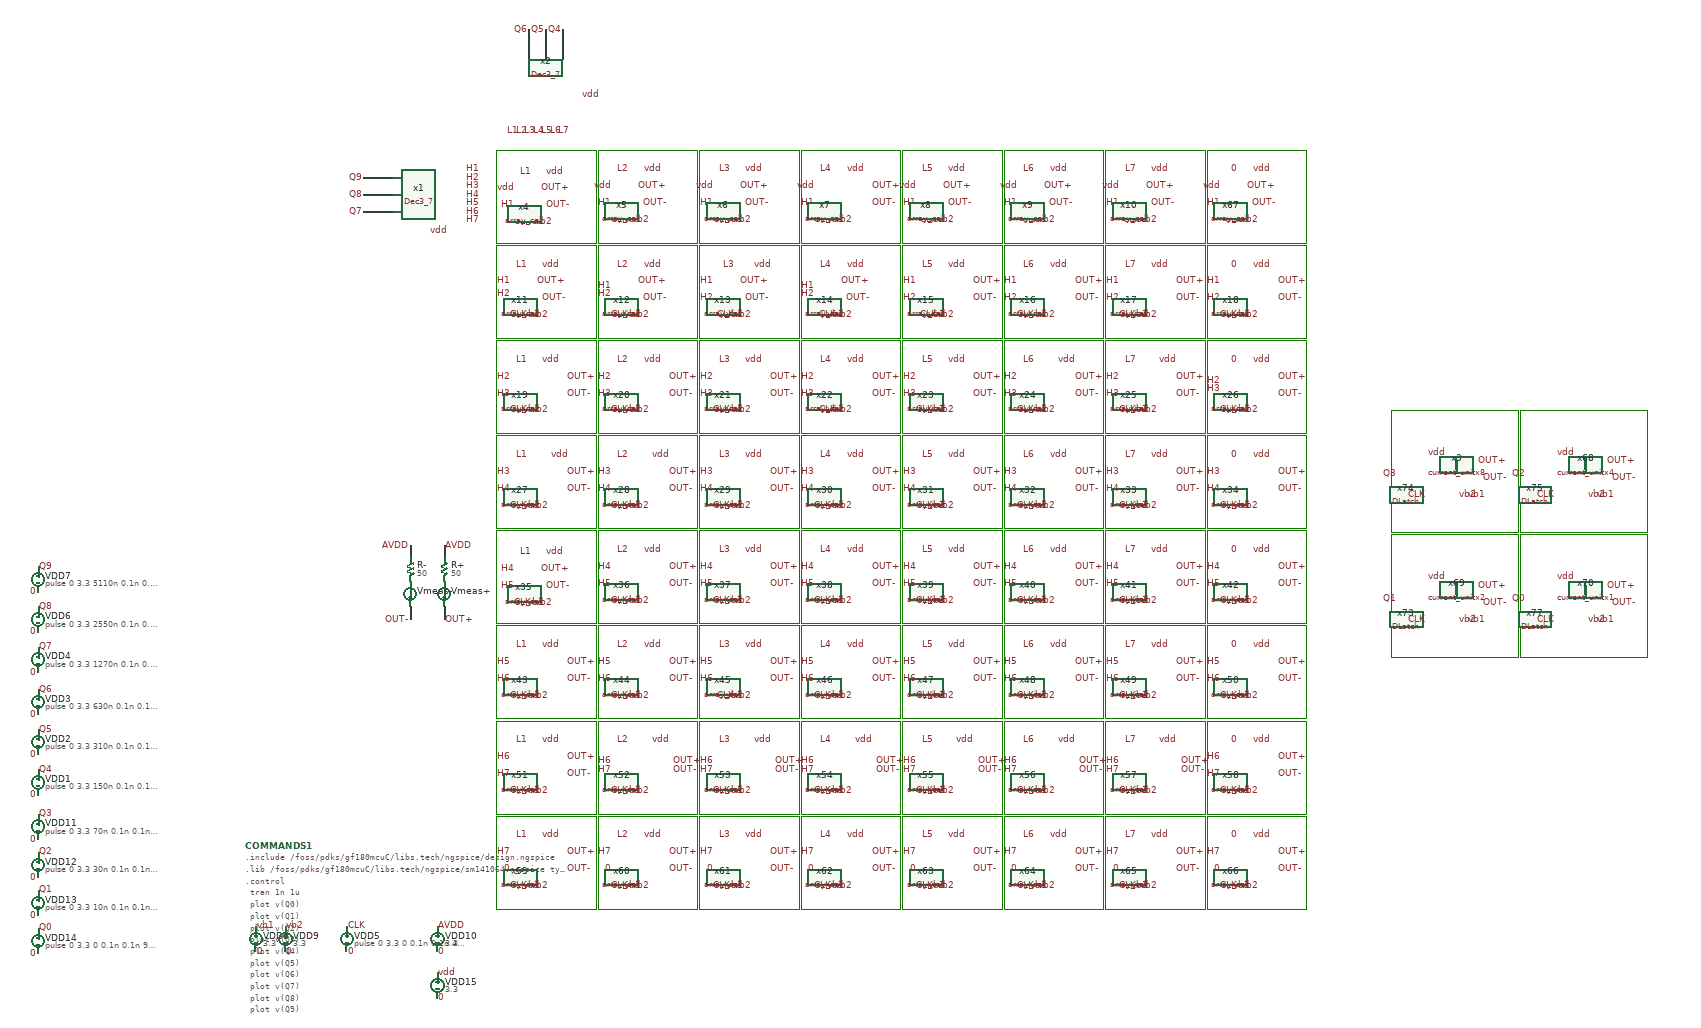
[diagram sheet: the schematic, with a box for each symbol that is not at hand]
v {xschem version=3.1.0 file_version=1.2
}
G {}
K {}
V {}
S {}
E {}
L 4 40 -1675 235 -1675 {}
L 4 235 -1895 235 -1675 {}
L 4 40 -1895 235 -1895 {}
L 4 0 -1895 40 -1895 {}
L 4 0 -1675 40 -1675 {}
L 4 0 -1895 0 -1675 {}
L 4 280 -1675 475 -1675 {}
L 4 475 -1895 475 -1675 {}
L 4 280 -1895 475 -1895 {}
L 4 240 -1895 280 -1895 {}
L 4 240 -1675 280 -1675 {}
L 4 240 -1895 240 -1675 {}
L 4 520 -1675 715 -1675 {}
L 4 715 -1895 715 -1675 {}
L 4 520 -1895 715 -1895 {}
L 4 480 -1895 520 -1895 {}
L 4 480 -1675 520 -1675 {}
L 4 480 -1895 480 -1675 {}
L 4 760 -1675 955 -1675 {}
L 4 955 -1895 955 -1675 {}
L 4 760 -1895 955 -1895 {}
L 4 720 -1895 760 -1895 {}
L 4 720 -1675 760 -1675 {}
L 4 720 -1895 720 -1675 {}
L 4 1000 -1675 1195 -1675 {}
L 4 1195 -1895 1195 -1675 {}
L 4 1000 -1895 1195 -1895 {}
L 4 960 -1895 1000 -1895 {}
L 4 960 -1675 1000 -1675 {}
L 4 960 -1895 960 -1675 {}
L 4 1240 -1675 1435 -1675 {}
L 4 1435 -1895 1435 -1675 {}
L 4 1240 -1895 1435 -1895 {}
L 4 1200 -1895 1240 -1895 {}
L 4 1200 -1675 1240 -1675 {}
L 4 1200 -1895 1200 -1675 {}
L 4 1480 -1675 1675 -1675 {}
L 4 1675 -1895 1675 -1675 {}
L 4 1480 -1895 1675 -1895 {}
L 4 1440 -1895 1480 -1895 {}
L 4 1440 -1675 1480 -1675 {}
L 4 1440 -1895 1440 -1675 {}
L 4 1720 -1675 1915 -1675 {}
L 4 1915 -1895 1915 -1675 {}
L 4 1720 -1895 1915 -1895 {}
L 4 1680 -1895 1720 -1895 {}
L 4 1680 -1675 1720 -1675 {}
L 4 1680 -1895 1680 -1675 {}
L 4 40 -1450 235 -1450 {}
L 4 235 -1670 235 -1450 {}
L 4 40 -1670 235 -1670 {}
L 4 0 -1670 40 -1670 {}
L 4 0 -1450 40 -1450 {}
L 4 0 -1670 0 -1450 {}
L 4 280 -1450 475 -1450 {}
L 4 475 -1670 475 -1450 {}
L 4 280 -1670 475 -1670 {}
L 4 240 -1670 280 -1670 {}
L 4 240 -1450 280 -1450 {}
L 4 240 -1670 240 -1450 {}
L 4 520 -1450 715 -1450 {}
L 4 715 -1670 715 -1450 {}
L 4 520 -1670 715 -1670 {}
L 4 480 -1670 520 -1670 {}
L 4 480 -1450 520 -1450 {}
L 4 480 -1670 480 -1450 {}
L 4 760 -1450 955 -1450 {}
L 4 955 -1670 955 -1450 {}
L 4 760 -1670 955 -1670 {}
L 4 720 -1670 760 -1670 {}
L 4 720 -1450 760 -1450 {}
L 4 720 -1670 720 -1450 {}
L 4 1000 -1450 1195 -1450 {}
L 4 1195 -1670 1195 -1450 {}
L 4 1000 -1670 1195 -1670 {}
L 4 960 -1670 1000 -1670 {}
L 4 960 -1450 1000 -1450 {}
L 4 960 -1670 960 -1450 {}
L 4 1240 -1450 1435 -1450 {}
L 4 1435 -1670 1435 -1450 {}
L 4 1240 -1670 1435 -1670 {}
L 4 1200 -1670 1240 -1670 {}
L 4 1200 -1450 1240 -1450 {}
L 4 1200 -1670 1200 -1450 {}
L 4 1480 -1450 1675 -1450 {}
L 4 1675 -1670 1675 -1450 {}
L 4 1480 -1670 1675 -1670 {}
L 4 1440 -1670 1480 -1670 {}
L 4 1440 -1450 1480 -1450 {}
L 4 1440 -1670 1440 -1450 {}
L 4 1720 -1450 1915 -1450 {}
L 4 1915 -1670 1915 -1450 {}
L 4 1720 -1670 1915 -1670 {}
L 4 1680 -1670 1720 -1670 {}
L 4 1680 -1450 1720 -1450 {}
L 4 1680 -1670 1680 -1450 {}
L 4 40 -1225 235 -1225 {}
L 4 235 -1445 235 -1225 {}
L 4 40 -1445 235 -1445 {}
L 4 0 -1445 40 -1445 {}
L 4 0 -1225 40 -1225 {}
L 4 0 -1445 0 -1225 {}
L 4 280 -1225 475 -1225 {}
L 4 475 -1445 475 -1225 {}
L 4 280 -1445 475 -1445 {}
L 4 240 -1445 280 -1445 {}
L 4 240 -1225 280 -1225 {}
L 4 240 -1445 240 -1225 {}
L 4 520 -1225 715 -1225 {}
L 4 715 -1445 715 -1225 {}
L 4 520 -1445 715 -1445 {}
L 4 480 -1445 520 -1445 {}
L 4 480 -1225 520 -1225 {}
L 4 480 -1445 480 -1225 {}
L 4 760 -1225 955 -1225 {}
L 4 955 -1445 955 -1225 {}
L 4 760 -1445 955 -1445 {}
L 4 720 -1445 760 -1445 {}
L 4 720 -1225 760 -1225 {}
L 4 720 -1445 720 -1225 {}
L 4 1000 -1225 1195 -1225 {}
L 4 1195 -1445 1195 -1225 {}
L 4 1000 -1445 1195 -1445 {}
L 4 960 -1445 1000 -1445 {}
L 4 960 -1225 1000 -1225 {}
L 4 960 -1445 960 -1225 {}
L 4 1240 -1225 1435 -1225 {}
L 4 1435 -1445 1435 -1225 {}
L 4 1240 -1445 1435 -1445 {}
L 4 1200 -1445 1240 -1445 {}
L 4 1200 -1225 1240 -1225 {}
L 4 1200 -1445 1200 -1225 {}
L 4 1480 -1225 1675 -1225 {}
L 4 1675 -1445 1675 -1225 {}
L 4 1480 -1445 1675 -1445 {}
L 4 1440 -1445 1480 -1445 {}
L 4 1440 -1225 1480 -1225 {}
L 4 1440 -1445 1440 -1225 {}
L 4 1720 -1225 1915 -1225 {}
L 4 1915 -1445 1915 -1225 {}
L 4 1720 -1445 1915 -1445 {}
L 4 1680 -1445 1720 -1445 {}
L 4 1680 -1225 1720 -1225 {}
L 4 1680 -1445 1680 -1225 {}
L 4 40 -1000 235 -1000 {}
L 4 235 -1220 235 -1000 {}
L 4 40 -1220 235 -1220 {}
L 4 0 -1220 40 -1220 {}
L 4 0 -1000 40 -1000 {}
L 4 0 -1220 0 -1000 {}
L 4 280 -1000 475 -1000 {}
L 4 475 -1220 475 -1000 {}
L 4 280 -1220 475 -1220 {}
L 4 240 -1220 280 -1220 {}
L 4 240 -1000 280 -1000 {}
L 4 240 -1220 240 -1000 {}
L 4 520 -1000 715 -1000 {}
L 4 715 -1220 715 -1000 {}
L 4 520 -1220 715 -1220 {}
L 4 480 -1220 520 -1220 {}
L 4 480 -1000 520 -1000 {}
L 4 480 -1220 480 -1000 {}
L 4 760 -1000 955 -1000 {}
L 4 955 -1220 955 -1000 {}
L 4 760 -1220 955 -1220 {}
L 4 720 -1220 760 -1220 {}
L 4 720 -1000 760 -1000 {}
L 4 720 -1220 720 -1000 {}
L 4 1000 -1000 1195 -1000 {}
L 4 1195 -1220 1195 -1000 {}
L 4 1000 -1220 1195 -1220 {}
L 4 960 -1220 1000 -1220 {}
L 4 960 -1000 1000 -1000 {}
L 4 960 -1220 960 -1000 {}
L 4 1240 -1000 1435 -1000 {}
L 4 1435 -1220 1435 -1000 {}
L 4 1240 -1220 1435 -1220 {}
L 4 1200 -1220 1240 -1220 {}
L 4 1200 -1000 1240 -1000 {}
L 4 1200 -1220 1200 -1000 {}
L 4 1480 -1000 1675 -1000 {}
L 4 1675 -1220 1675 -1000 {}
L 4 1480 -1220 1675 -1220 {}
L 4 1440 -1220 1480 -1220 {}
L 4 1440 -1000 1480 -1000 {}
L 4 1440 -1220 1440 -1000 {}
L 4 1720 -1000 1915 -1000 {}
L 4 1915 -1220 1915 -1000 {}
L 4 1720 -1220 1915 -1220 {}
L 4 1680 -1220 1720 -1220 {}
L 4 1680 -1000 1720 -1000 {}
L 4 1680 -1220 1680 -1000 {}
L 4 40 -775 235 -775 {}
L 4 235 -995 235 -775 {}
L 4 40 -995 235 -995 {}
L 4 0 -995 40 -995 {}
L 4 0 -775 40 -775 {}
L 4 0 -995 0 -775 {}
L 4 280 -775 475 -775 {}
L 4 475 -995 475 -775 {}
L 4 280 -995 475 -995 {}
L 4 240 -995 280 -995 {}
L 4 240 -775 280 -775 {}
L 4 240 -995 240 -775 {}
L 4 520 -775 715 -775 {}
L 4 715 -995 715 -775 {}
L 4 520 -995 715 -995 {}
L 4 480 -995 520 -995 {}
L 4 480 -775 520 -775 {}
L 4 480 -995 480 -775 {}
L 4 760 -775 955 -775 {}
L 4 955 -995 955 -775 {}
L 4 760 -995 955 -995 {}
L 4 720 -995 760 -995 {}
L 4 720 -775 760 -775 {}
L 4 720 -995 720 -775 {}
L 4 1000 -775 1195 -775 {}
L 4 1195 -995 1195 -775 {}
L 4 1000 -995 1195 -995 {}
L 4 960 -995 1000 -995 {}
L 4 960 -775 1000 -775 {}
L 4 960 -995 960 -775 {}
L 4 1240 -775 1435 -775 {}
L 4 1435 -995 1435 -775 {}
L 4 1240 -995 1435 -995 {}
L 4 1200 -995 1240 -995 {}
L 4 1200 -775 1240 -775 {}
L 4 1200 -995 1200 -775 {}
L 4 1480 -775 1675 -775 {}
L 4 1675 -995 1675 -775 {}
L 4 1480 -995 1675 -995 {}
L 4 1440 -995 1480 -995 {}
L 4 1440 -775 1480 -775 {}
L 4 1440 -995 1440 -775 {}
L 4 1720 -775 1915 -775 {}
L 4 1915 -995 1915 -775 {}
L 4 1720 -995 1915 -995 {}
L 4 1680 -995 1720 -995 {}
L 4 1680 -775 1720 -775 {}
L 4 1680 -995 1680 -775 {}
L 4 40 -550 235 -550 {}
L 4 235 -770 235 -550 {}
L 4 40 -770 235 -770 {}
L 4 0 -770 40 -770 {}
L 4 0 -550 40 -550 {}
L 4 0 -770 0 -550 {}
L 4 280 -550 475 -550 {}
L 4 475 -770 475 -550 {}
L 4 280 -770 475 -770 {}
L 4 240 -770 280 -770 {}
L 4 240 -550 280 -550 {}
L 4 240 -770 240 -550 {}
L 4 520 -550 715 -550 {}
L 4 715 -770 715 -550 {}
L 4 520 -770 715 -770 {}
L 4 480 -770 520 -770 {}
L 4 480 -550 520 -550 {}
L 4 480 -770 480 -550 {}
L 4 760 -550 955 -550 {}
L 4 955 -770 955 -550 {}
L 4 760 -770 955 -770 {}
L 4 720 -770 760 -770 {}
L 4 720 -550 760 -550 {}
L 4 720 -770 720 -550 {}
L 4 1000 -550 1195 -550 {}
L 4 1195 -770 1195 -550 {}
L 4 1000 -770 1195 -770 {}
L 4 960 -770 1000 -770 {}
L 4 960 -550 1000 -550 {}
L 4 960 -770 960 -550 {}
L 4 1240 -550 1435 -550 {}
L 4 1435 -770 1435 -550 {}
L 4 1240 -770 1435 -770 {}
L 4 1200 -770 1240 -770 {}
L 4 1200 -550 1240 -550 {}
L 4 1200 -770 1200 -550 {}
L 4 1480 -550 1675 -550 {}
L 4 1675 -770 1675 -550 {}
L 4 1480 -770 1675 -770 {}
L 4 1440 -770 1480 -770 {}
L 4 1440 -550 1480 -550 {}
L 4 1440 -770 1440 -550 {}
L 4 1720 -550 1915 -550 {}
L 4 1915 -770 1915 -550 {}
L 4 1720 -770 1915 -770 {}
L 4 1680 -770 1720 -770 {}
L 4 1680 -550 1720 -550 {}
L 4 1680 -770 1680 -550 {}
L 4 40 -325 235 -325 {}
L 4 235 -545 235 -325 {}
L 4 40 -545 235 -545 {}
L 4 0 -545 40 -545 {}
L 4 0 -325 40 -325 {}
L 4 0 -545 0 -325 {}
L 4 280 -325 475 -325 {}
L 4 475 -545 475 -325 {}
L 4 280 -545 475 -545 {}
L 4 240 -545 280 -545 {}
L 4 240 -325 280 -325 {}
L 4 240 -545 240 -325 {}
L 4 520 -325 715 -325 {}
L 4 715 -545 715 -325 {}
L 4 520 -545 715 -545 {}
L 4 480 -545 520 -545 {}
L 4 480 -325 520 -325 {}
L 4 480 -545 480 -325 {}
L 4 760 -325 955 -325 {}
L 4 955 -545 955 -325 {}
L 4 760 -545 955 -545 {}
L 4 720 -545 760 -545 {}
L 4 720 -325 760 -325 {}
L 4 720 -545 720 -325 {}
L 4 1000 -325 1195 -325 {}
L 4 1195 -545 1195 -325 {}
L 4 1000 -545 1195 -545 {}
L 4 960 -545 1000 -545 {}
L 4 960 -325 1000 -325 {}
L 4 960 -545 960 -325 {}
L 4 1240 -325 1435 -325 {}
L 4 1435 -545 1435 -325 {}
L 4 1240 -545 1435 -545 {}
L 4 1200 -545 1240 -545 {}
L 4 1200 -325 1240 -325 {}
L 4 1200 -545 1200 -325 {}
L 4 1480 -325 1675 -325 {}
L 4 1675 -545 1675 -325 {}
L 4 1480 -545 1675 -545 {}
L 4 1440 -545 1480 -545 {}
L 4 1440 -325 1480 -325 {}
L 4 1440 -545 1440 -325 {}
L 4 1720 -325 1915 -325 {}
L 4 1915 -545 1915 -325 {}
L 4 1720 -545 1915 -545 {}
L 4 1680 -545 1720 -545 {}
L 4 1680 -325 1720 -325 {}
L 4 1680 -545 1680 -325 {}
L 4 40 -100 235 -100 {}
L 4 235 -320 235 -100 {}
L 4 40 -320 235 -320 {}
L 4 0 -320 40 -320 {}
L 4 0 -100 40 -100 {}
L 4 0 -320 0 -100 {}
L 4 280 -100 475 -100 {}
L 4 475 -320 475 -100 {}
L 4 280 -320 475 -320 {}
L 4 240 -320 280 -320 {}
L 4 240 -100 280 -100 {}
L 4 240 -320 240 -100 {}
L 4 520 -100 715 -100 {}
L 4 715 -320 715 -100 {}
L 4 520 -320 715 -320 {}
L 4 480 -320 520 -320 {}
L 4 480 -100 520 -100 {}
L 4 480 -320 480 -100 {}
L 4 760 -100 955 -100 {}
L 4 955 -320 955 -100 {}
L 4 760 -320 955 -320 {}
L 4 720 -320 760 -320 {}
L 4 720 -100 760 -100 {}
L 4 720 -320 720 -100 {}
L 4 1000 -100 1195 -100 {}
L 4 1195 -320 1195 -100 {}
L 4 1000 -320 1195 -320 {}
L 4 960 -320 1000 -320 {}
L 4 960 -100 1000 -100 {}
L 4 960 -320 960 -100 {}
L 4 1240 -100 1435 -100 {}
L 4 1435 -320 1435 -100 {}
L 4 1240 -320 1435 -320 {}
L 4 1200 -320 1240 -320 {}
L 4 1200 -100 1240 -100 {}
L 4 1200 -320 1200 -100 {}
L 4 1480 -100 1675 -100 {}
L 4 1675 -320 1675 -100 {}
L 4 1480 -320 1675 -320 {}
L 4 1440 -320 1480 -320 {}
L 4 1440 -100 1480 -100 {}
L 4 1440 -320 1440 -100 {}
L 4 1720 -100 1915 -100 {}
L 4 1915 -320 1915 -100 {}
L 4 1720 -320 1915 -320 {}
L 4 1680 -320 1720 -320 {}
L 4 1680 -100 1720 -100 {}
L 4 1680 -320 1680 -100 {}
L 4 2115 -1230 2115 -990 {}
L 4 2115 -990 2415 -990 {}
L 4 2415 -1240 2415 -990 {}
L 4 2115 -1240 2115 -1230 {}
L 4 2115 -1280 2115 -1240 {}
L 4 2115 -1280 2415 -1280 {}
L 4 2415 -1280 2415 -1240 {}
L 4 2420 -1230 2420 -990 {}
L 4 2420 -990 2720 -990 {}
L 4 2720 -1240 2720 -990 {}
L 4 2420 -1240 2420 -1230 {}
L 4 2420 -1280 2420 -1240 {}
L 4 2420 -1280 2720 -1280 {}
L 4 2720 -1280 2720 -1240 {}
L 4 2115 -935 2115 -695 {}
L 4 2115 -695 2415 -695 {}
L 4 2415 -945 2415 -695 {}
L 4 2115 -945 2115 -935 {}
L 4 2115 -985 2115 -945 {}
L 4 2115 -985 2415 -985 {}
L 4 2415 -985 2415 -945 {}
L 4 2420 -935 2420 -695 {}
L 4 2420 -695 2720 -695 {}
L 4 2720 -945 2720 -695 {}
L 4 2420 -945 2420 -935 {}
L 4 2420 -985 2420 -945 {}
L 4 2420 -985 2720 -985 {}
L 4 2720 -985 2720 -945 {}
N 155 -2180 155 -2110 {
lab=Q4}
N 115 -2180 115 -2110 {
lab=Q5}
N 75 -2180 75 -2110 {
lab=Q6}
N -315 -1750 -245 -1750 {
lab=Q7}
N -315 -1790 -245 -1790 {
lab=Q8}
N -315 -1830 -245 -1830 {
lab=Q9}
N 2270 -1160 2270 -1140 {
lab=#net1}
N 2575 -1160 2575 -1140 {
lab=#net2}
N 2270 -865 2270 -845 {
lab=#net3}
N 2575 -865 2575 -845 {
lab=#net4}
N -125 -960 -125 -935 {
lab=AVDD}
N -205 -960 -205 -935 {
lab=AVDD}
N -125 -815 -125 -785 {
lab=OUT+}
N -205 -815 -205 -785 {
lab=OUT-}
C {devices/lab_pin.sym} 155 -2180 1 0 {name=p1 sig_type=std_logic lab=Q4}
C {devices/lab_pin.sym} 115 -2180 1 0 {name=p2 sig_type=std_logic lab=Q5}
C {devices/lab_pin.sym} 75 -2180 1 0 {name=p3 sig_type=std_logic lab=Q6}
C {devices/lab_pin.sym} 55 -1940 1 1 {name=p13 sig_type=std_logic lab=L1}
C {devices/lab_pin.sym} 75 -1940 1 1 {name=p17 sig_type=std_logic lab=L2}
C {devices/lab_pin.sym} 95 -1940 1 1 {name=p18 sig_type=std_logic lab=L3}
C {devices/lab_pin.sym} 115 -1940 1 1 {name=p19 sig_type=std_logic lab=L4}
C {devices/lab_pin.sym} 135 -1940 1 1 {name=p20 sig_type=std_logic lab=L5}
C {devices/lab_pin.sym} 155 -1940 1 1 {name=p21 sig_type=std_logic lab=L6}
C {devices/lab_pin.sym} 175 -1940 1 1 {name=p22 sig_type=std_logic lab=L7}
C {devices/lab_pin.sym} 200 -2025 0 1 {name=p106 sig_type=std_logic lab=vdd}
C {devices/lab_pin.sym} -315 -1750 2 1 {name=p4 sig_type=std_logic lab=Q7}
C {devices/lab_pin.sym} -315 -1790 2 1 {name=p5 sig_type=std_logic lab=Q8}
C {devices/lab_pin.sym} -315 -1830 2 1 {name=p6 sig_type=std_logic lab=Q9}
C {devices/lab_pin.sym} -75 -1850 2 0 {name=p7 sig_type=std_logic lab=H1}
C {devices/lab_pin.sym} -75 -1830 2 0 {name=p8 sig_type=std_logic lab=H2}
C {devices/lab_pin.sym} -75 -1810 2 0 {name=p9 sig_type=std_logic lab=H3}
C {devices/lab_pin.sym} -75 -1790 2 0 {name=p10 sig_type=std_logic lab=H4}
C {devices/lab_pin.sym} -75 -1770 2 0 {name=p11 sig_type=std_logic lab=H5}
C {devices/lab_pin.sym} -75 -1750 2 0 {name=p12 sig_type=std_logic lab=H6}
C {devices/lab_pin.sym} -75 -1730 2 0 {name=p14 sig_type=std_logic lab=H7}
C {devices/lab_pin.sym} -160 -1705 2 0 {name=p15 sig_type=std_logic lab=vdd}
C {devices/lab_pin.sym} 45 -1805 1 0 {name=p16 sig_type=std_logic lab=vdd}
C {devices/lab_pin.sym} 115 -1845 0 1 {name=p23 sig_type=std_logic lab=vdd}
C {devices/lab_pin.sym} 115 -1725 1 1 {name=p24 sig_type=std_logic lab=vb1}
C {devices/lab_pin.sym} 135 -1725 1 1 {name=p25 sig_type=std_logic lab=vb2}
C {devices/lab_pin.sym} 85 -1725 1 1 {name=p26 sig_type=std_logic lab=CLK}
C {devices/lab_pin.sym} 85 -1845 3 1 {name=p32 sig_type=std_logic lab=L1}
C {devices/lab_pin.sym} 275 -1810 1 0 {name=p27 sig_type=std_logic lab=vdd}
C {devices/lab_pin.sym} 345 -1850 0 1 {name=p28 sig_type=std_logic lab=vdd}
C {devices/lab_pin.sym} 345 -1730 1 1 {name=p29 sig_type=std_logic lab=vb1}
C {devices/lab_pin.sym} 365 -1730 1 1 {name=p30 sig_type=std_logic lab=vb2}
C {devices/lab_pin.sym} 315 -1730 1 1 {name=p31 sig_type=std_logic lab=CLK}
C {devices/lab_pin.sym} 315 -1850 3 1 {name=p33 sig_type=std_logic lab=L2}
C {devices/lab_pin.sym} 515 -1810 1 0 {name=p34 sig_type=std_logic lab=vdd}
C {devices/lab_pin.sym} 585 -1850 0 1 {name=p35 sig_type=std_logic lab=vdd}
C {devices/lab_pin.sym} 585 -1730 1 1 {name=p36 sig_type=std_logic lab=vb1}
C {devices/lab_pin.sym} 605 -1730 1 1 {name=p37 sig_type=std_logic lab=vb2}
C {devices/lab_pin.sym} 555 -1730 1 1 {name=p38 sig_type=std_logic lab=CLK}
C {devices/lab_pin.sym} 555 -1850 3 1 {name=p39 sig_type=std_logic lab=L3}
C {devices/lab_pin.sym} 45 -1765 2 1 {name=p40 sig_type=std_logic lab=H1}
C {devices/lab_pin.sym} 275 -1770 2 1 {name=p41 sig_type=std_logic lab=H1}
C {devices/lab_pin.sym} 515 -1770 2 1 {name=p42 sig_type=std_logic lab=H1}
C {devices/lab_pin.sym} 175 -1805 3 1 {name=p43 sig_type=std_logic lab=OUT+}
C {devices/lab_pin.sym} 405 -1810 3 1 {name=p44 sig_type=std_logic lab=OUT+}
C {devices/lab_pin.sym} 175 -1765 1 1 {name=p45 sig_type=std_logic lab=OUT-}
C {devices/lab_pin.sym} 405 -1770 1 1 {name=p46 sig_type=std_logic lab=OUT-}
C {devices/lab_pin.sym} 645 -1810 3 1 {name=p47 sig_type=std_logic lab=OUT+}
C {devices/lab_pin.sym} 645 -1770 1 1 {name=p48 sig_type=std_logic lab=OUT-}
C {devices/lab_pin.sym} 755 -1810 1 0 {name=p49 sig_type=std_logic lab=vdd}
C {devices/lab_pin.sym} 825 -1850 0 1 {name=p50 sig_type=std_logic lab=vdd}
C {devices/lab_pin.sym} 825 -1730 1 1 {name=p51 sig_type=std_logic lab=vb1}
C {devices/lab_pin.sym} 845 -1730 1 1 {name=p52 sig_type=std_logic lab=vb2}
C {devices/lab_pin.sym} 795 -1730 1 1 {name=p53 sig_type=std_logic lab=CLK}
C {devices/lab_pin.sym} 795 -1850 3 1 {name=p54 sig_type=std_logic lab=L4}
C {devices/lab_pin.sym} 995 -1810 1 0 {name=p55 sig_type=std_logic lab=vdd}
C {devices/lab_pin.sym} 1065 -1850 0 1 {name=p56 sig_type=std_logic lab=vdd}
C {devices/lab_pin.sym} 1065 -1730 1 1 {name=p57 sig_type=std_logic lab=vb1}
C {devices/lab_pin.sym} 1085 -1730 1 1 {name=p58 sig_type=std_logic lab=vb2}
C {devices/lab_pin.sym} 1045 -1730 1 1 {name=p59 sig_type=std_logic lab=CLK}
C {devices/lab_pin.sym} 1035 -1850 3 1 {name=p60 sig_type=std_logic lab=L5}
C {devices/lab_pin.sym} 1235 -1810 1 0 {name=p61 sig_type=std_logic lab=vdd}
C {devices/lab_pin.sym} 1305 -1850 0 1 {name=p62 sig_type=std_logic lab=vdd}
C {devices/lab_pin.sym} 1305 -1730 1 1 {name=p63 sig_type=std_logic lab=vb1}
C {devices/lab_pin.sym} 1325 -1730 1 1 {name=p64 sig_type=std_logic lab=vb2}
C {devices/lab_pin.sym} 1285 -1730 1 1 {name=p65 sig_type=std_logic lab=CLK}
C {devices/lab_pin.sym} 1275 -1850 3 1 {name=p66 sig_type=std_logic lab=L6}
C {devices/lab_pin.sym} 755 -1770 2 1 {name=p67 sig_type=std_logic lab=H1}
C {devices/lab_pin.sym} 995 -1770 2 1 {name=p68 sig_type=std_logic lab=H1}
C {devices/lab_pin.sym} 1235 -1770 2 1 {name=p69 sig_type=std_logic lab=H1}
C {devices/lab_pin.sym} 885 -1810 0 1 {name=p70 sig_type=std_logic lab=OUT+}
C {devices/lab_pin.sym} 1125 -1810 3 1 {name=p71 sig_type=std_logic lab=OUT+}
C {devices/lab_pin.sym} 885 -1770 0 1 {name=p72 sig_type=std_logic lab=OUT-}
C {devices/lab_pin.sym} 1125 -1770 1 1 {name=p73 sig_type=std_logic lab=OUT-}
C {devices/lab_pin.sym} 1365 -1810 3 1 {name=p74 sig_type=std_logic lab=OUT+}
C {devices/lab_pin.sym} 1365 -1770 1 1 {name=p75 sig_type=std_logic lab=OUT-}
C {devices/lab_pin.sym} 1475 -1810 1 0 {name=p76 sig_type=std_logic lab=vdd}
C {devices/lab_pin.sym} 1545 -1850 0 1 {name=p77 sig_type=std_logic lab=vdd}
C {devices/lab_pin.sym} 1545 -1730 1 1 {name=p78 sig_type=std_logic lab=vb1}
C {devices/lab_pin.sym} 1565 -1730 1 1 {name=p79 sig_type=std_logic lab=vb2}
C {devices/lab_pin.sym} 1525 -1730 1 1 {name=p80 sig_type=std_logic lab=CLK}
C {devices/lab_pin.sym} 1515 -1850 3 1 {name=p81 sig_type=std_logic lab=L7}
C {devices/lab_pin.sym} 1475 -1770 2 1 {name=p82 sig_type=std_logic lab=H1}
C {devices/lab_pin.sym} 1605 -1810 3 1 {name=p83 sig_type=std_logic lab=OUT+}
C {devices/lab_pin.sym} 1605 -1770 1 1 {name=p84 sig_type=std_logic lab=OUT-}
C {devices/lab_pin.sym} 1715 -1810 1 0 {name=p85 sig_type=std_logic lab=vdd}
C {devices/lab_pin.sym} 1785 -1850 0 1 {name=p86 sig_type=std_logic lab=vdd}
C {devices/lab_pin.sym} 1785 -1730 1 1 {name=p87 sig_type=std_logic lab=vb1}
C {devices/lab_pin.sym} 1805 -1730 1 1 {name=p88 sig_type=std_logic lab=vb2}
C {devices/lab_pin.sym} 1765 -1730 1 1 {name=p89 sig_type=std_logic lab=CLK}
C {devices/lab_pin.sym} 1755 -1850 3 1 {name=p90 sig_type=std_logic lab=0}
C {devices/lab_pin.sym} 1715 -1770 2 1 {name=p91 sig_type=std_logic lab=H1}
C {devices/lab_pin.sym} 1845 -1810 3 1 {name=p92 sig_type=std_logic lab=OUT+}
C {devices/lab_pin.sym} 1845 -1770 1 1 {name=p93 sig_type=std_logic lab=OUT-}
C {devices/lab_pin.sym} 35 -1585 1 0 {name=p94 sig_type=std_logic lab=H1}
C {analog/array_cell.sym} 55 -1525 0 0 {name=x11}
C {devices/lab_pin.sym} 105 -1625 0 1 {name=p95 sig_type=std_logic lab=vdd}
C {devices/lab_pin.sym} 105 -1505 1 1 {name=p96 sig_type=std_logic lab=vb1}
C {devices/lab_pin.sym} 125 -1505 1 1 {name=p97 sig_type=std_logic lab=vb2}
C {devices/lab_pin.sym} 75 -1505 1 1 {name=p98 sig_type=std_logic lab=CLK}
C {devices/lab_pin.sym} 75 -1625 3 1 {name=p99 sig_type=std_logic lab=L1}
C {devices/lab_pin.sym} 275 -1575 1 0 {name=p100 sig_type=std_logic lab=H1}
C {analog/array_cell.sym} 295 -1525 0 0 {name=x12}
C {devices/lab_pin.sym} 345 -1625 0 1 {name=p101 sig_type=std_logic lab=vdd}
C {devices/lab_pin.sym} 345 -1505 1 1 {name=p102 sig_type=std_logic lab=vb1}
C {devices/lab_pin.sym} 365 -1505 1 1 {name=p103 sig_type=std_logic lab=vb2}
C {devices/lab_pin.sym} 315 -1505 1 1 {name=p104 sig_type=std_logic lab=CLK}
C {devices/lab_pin.sym} 315 -1625 3 1 {name=p105 sig_type=std_logic lab=L2}
C {devices/lab_pin.sym} 515 -1585 1 0 {name=p107 sig_type=std_logic lab=H1}
C {analog/array_cell.sym} 535 -1525 0 0 {name=x13}
C {devices/lab_pin.sym} 605 -1625 0 1 {name=p108 sig_type=std_logic lab=vdd}
C {devices/lab_pin.sym} 585 -1505 1 1 {name=p109 sig_type=std_logic lab=vb1}
C {devices/lab_pin.sym} 605 -1505 1 1 {name=p110 sig_type=std_logic lab=vb2}
C {devices/lab_pin.sym} 565 -1505 1 1 {name=p111 sig_type=std_logic lab=CLK}
C {devices/lab_pin.sym} 565 -1625 3 1 {name=p112 sig_type=std_logic lab=L3}
C {devices/lab_pin.sym} 35 -1555 2 1 {name=p113 sig_type=std_logic lab=H2}
C {devices/lab_pin.sym} 275 -1555 2 1 {name=p114 sig_type=std_logic lab=H2}
C {devices/lab_pin.sym} 515 -1545 2 1 {name=p115 sig_type=std_logic lab=H2}
C {devices/lab_pin.sym} 165 -1585 3 1 {name=p116 sig_type=std_logic lab=OUT+}
C {devices/lab_pin.sym} 405 -1585 3 1 {name=p117 sig_type=std_logic lab=OUT+}
C {devices/lab_pin.sym} 165 -1545 1 1 {name=p118 sig_type=std_logic lab=OUT-}
C {devices/lab_pin.sym} 405 -1545 1 1 {name=p119 sig_type=std_logic lab=OUT-}
C {devices/lab_pin.sym} 645 -1585 3 1 {name=p120 sig_type=std_logic lab=OUT+}
C {devices/lab_pin.sym} 645 -1545 1 1 {name=p121 sig_type=std_logic lab=OUT-}
C {devices/lab_pin.sym} 755 -1575 1 0 {name=p122 sig_type=std_logic lab=H1}
C {analog/array_cell.sym} 775 -1525 0 0 {name=x14}
C {devices/lab_pin.sym} 825 -1625 0 1 {name=p123 sig_type=std_logic lab=vdd}
C {devices/lab_pin.sym} 825 -1505 1 1 {name=p124 sig_type=std_logic lab=vb1}
C {devices/lab_pin.sym} 845 -1505 1 1 {name=p125 sig_type=std_logic lab=vb2}
C {devices/lab_pin.sym} 805 -1505 1 1 {name=p126 sig_type=std_logic lab=CLK}
C {devices/lab_pin.sym} 795 -1625 3 1 {name=p127 sig_type=std_logic lab=L4}
C {devices/lab_pin.sym} 995 -1585 1 0 {name=p128 sig_type=std_logic lab=H1}
C {analog/array_cell.sym} 1015 -1525 0 0 {name=x15}
C {devices/lab_pin.sym} 1065 -1625 0 1 {name=p129 sig_type=std_logic lab=vdd}
C {devices/lab_pin.sym} 1065 -1505 1 1 {name=p130 sig_type=std_logic lab=vb1}
C {devices/lab_pin.sym} 1085 -1505 1 1 {name=p131 sig_type=std_logic lab=vb2}
C {devices/lab_pin.sym} 1045 -1505 1 1 {name=p132 sig_type=std_logic lab=CLK}
C {devices/lab_pin.sym} 1035 -1625 3 1 {name=p133 sig_type=std_logic lab=L5}
C {devices/lab_pin.sym} 1235 -1585 1 0 {name=p134 sig_type=std_logic lab=H1}
C {analog/array_cell.sym} 1255 -1525 0 0 {name=x16}
C {devices/lab_pin.sym} 1305 -1625 0 1 {name=p135 sig_type=std_logic lab=vdd}
C {devices/lab_pin.sym} 1305 -1505 1 1 {name=p136 sig_type=std_logic lab=vb1}
C {devices/lab_pin.sym} 1325 -1505 1 1 {name=p137 sig_type=std_logic lab=vb2}
C {devices/lab_pin.sym} 1275 -1505 1 1 {name=p138 sig_type=std_logic lab=CLK}
C {devices/lab_pin.sym} 1275 -1625 3 1 {name=p139 sig_type=std_logic lab=L6}
C {devices/lab_pin.sym} 755 -1555 2 1 {name=p140 sig_type=std_logic lab=H2}
C {devices/lab_pin.sym} 995 -1545 2 1 {name=p141 sig_type=std_logic lab=H2}
C {devices/lab_pin.sym} 1235 -1545 2 1 {name=p142 sig_type=std_logic lab=H2}
C {devices/lab_pin.sym} 885 -1585 3 1 {name=p143 sig_type=std_logic lab=OUT+}
C {devices/lab_pin.sym} 1125 -1585 0 1 {name=p144 sig_type=std_logic lab=OUT+}
C {devices/lab_pin.sym} 885 -1545 1 1 {name=p145 sig_type=std_logic lab=OUT-}
C {devices/lab_pin.sym} 1125 -1545 0 1 {name=p146 sig_type=std_logic lab=OUT-}
C {devices/lab_pin.sym} 1365 -1585 0 1 {name=p147 sig_type=std_logic lab=OUT+}
C {devices/lab_pin.sym} 1365 -1545 0 1 {name=p148 sig_type=std_logic lab=OUT-}
C {devices/lab_pin.sym} 1475 -1585 1 0 {name=p149 sig_type=std_logic lab=H1}
C {analog/array_cell.sym} 1495 -1525 0 0 {name=x17}
C {devices/lab_pin.sym} 1545 -1625 0 1 {name=p150 sig_type=std_logic lab=vdd}
C {devices/lab_pin.sym} 1545 -1505 1 1 {name=p151 sig_type=std_logic lab=vb1}
C {devices/lab_pin.sym} 1565 -1505 1 1 {name=p152 sig_type=std_logic lab=vb2}
C {devices/lab_pin.sym} 1515 -1505 1 1 {name=p153 sig_type=std_logic lab=CLK}
C {devices/lab_pin.sym} 1515 -1625 3 1 {name=p154 sig_type=std_logic lab=L7}
C {devices/lab_pin.sym} 1475 -1545 2 1 {name=p155 sig_type=std_logic lab=H2}
C {devices/lab_pin.sym} 1605 -1585 0 1 {name=p156 sig_type=std_logic lab=OUT+}
C {devices/lab_pin.sym} 1605 -1545 0 1 {name=p157 sig_type=std_logic lab=OUT-}
C {devices/lab_pin.sym} 1715 -1585 1 0 {name=p158 sig_type=std_logic lab=H1}
C {analog/array_cell.sym} 1735 -1525 0 0 {name=x18}
C {devices/lab_pin.sym} 1785 -1625 0 1 {name=p159 sig_type=std_logic lab=vdd}
C {devices/lab_pin.sym} 1785 -1505 1 1 {name=p160 sig_type=std_logic lab=vb1}
C {devices/lab_pin.sym} 1805 -1505 1 1 {name=p161 sig_type=std_logic lab=vb2}
C {devices/lab_pin.sym} 1755 -1505 1 1 {name=p162 sig_type=std_logic lab=CLK}
C {devices/lab_pin.sym} 1755 -1625 3 1 {name=p163 sig_type=std_logic lab=0}
C {devices/lab_pin.sym} 1715 -1545 2 1 {name=p164 sig_type=std_logic lab=H2}
C {devices/lab_pin.sym} 1845 -1585 0 1 {name=p165 sig_type=std_logic lab=OUT+}
C {devices/lab_pin.sym} 1845 -1545 0 1 {name=p166 sig_type=std_logic lab=OUT-}
C {devices/lab_pin.sym} 35 -1360 1 0 {name=p167 sig_type=std_logic lab=H2}
C {analog/array_cell.sym} 55 -1300 0 0 {name=x19}
C {devices/lab_pin.sym} 105 -1400 0 1 {name=p168 sig_type=std_logic lab=vdd}
C {devices/lab_pin.sym} 105 -1280 1 1 {name=p169 sig_type=std_logic lab=vb1}
C {devices/lab_pin.sym} 125 -1280 1 1 {name=p170 sig_type=std_logic lab=vb2}
C {devices/lab_pin.sym} 75 -1280 1 1 {name=p171 sig_type=std_logic lab=CLK}
C {devices/lab_pin.sym} 75 -1400 3 1 {name=p172 sig_type=std_logic lab=L1}
C {analog/array_cell.sym} 295 -1300 0 0 {name=x20}
C {devices/lab_pin.sym} 345 -1400 0 1 {name=p174 sig_type=std_logic lab=vdd}
C {devices/lab_pin.sym} 345 -1280 1 1 {name=p175 sig_type=std_logic lab=vb1}
C {devices/lab_pin.sym} 365 -1280 1 1 {name=p176 sig_type=std_logic lab=vb2}
C {devices/lab_pin.sym} 315 -1280 1 1 {name=p177 sig_type=std_logic lab=CLK}
C {devices/lab_pin.sym} 315 -1400 3 1 {name=p178 sig_type=std_logic lab=L2}
C {analog/array_cell.sym} 535 -1300 0 0 {name=x21}
C {devices/lab_pin.sym} 585 -1400 0 1 {name=p180 sig_type=std_logic lab=vdd}
C {devices/lab_pin.sym} 585 -1280 1 1 {name=p181 sig_type=std_logic lab=vb1}
C {devices/lab_pin.sym} 605 -1280 1 1 {name=p182 sig_type=std_logic lab=vb2}
C {devices/lab_pin.sym} 555 -1280 1 1 {name=p183 sig_type=std_logic lab=CLK}
C {devices/lab_pin.sym} 555 -1400 3 1 {name=p184 sig_type=std_logic lab=L3}
C {devices/lab_pin.sym} 35 -1320 2 1 {name=p185 sig_type=std_logic lab=H3}
C {devices/lab_pin.sym} 165 -1360 0 1 {name=p188 sig_type=std_logic lab=OUT+}
C {devices/lab_pin.sym} 405 -1360 0 1 {name=p189 sig_type=std_logic lab=OUT+}
C {devices/lab_pin.sym} 165 -1320 0 1 {name=p190 sig_type=std_logic lab=OUT-}
C {devices/lab_pin.sym} 405 -1320 0 1 {name=p191 sig_type=std_logic lab=OUT-}
C {devices/lab_pin.sym} 645 -1360 0 1 {name=p192 sig_type=std_logic lab=OUT+}
C {devices/lab_pin.sym} 645 -1320 0 1 {name=p193 sig_type=std_logic lab=OUT-}
C {analog/array_cell.sym} 775 -1300 0 0 {name=x22}
C {devices/lab_pin.sym} 825 -1400 0 1 {name=p195 sig_type=std_logic lab=vdd}
C {devices/lab_pin.sym} 825 -1280 1 1 {name=p196 sig_type=std_logic lab=vb1}
C {devices/lab_pin.sym} 845 -1280 1 1 {name=p197 sig_type=std_logic lab=vb2}
C {devices/lab_pin.sym} 805 -1280 1 1 {name=p198 sig_type=std_logic lab=CLK}
C {devices/lab_pin.sym} 795 -1400 3 1 {name=p199 sig_type=std_logic lab=L4}
C {analog/array_cell.sym} 1015 -1300 0 0 {name=x23}
C {devices/lab_pin.sym} 1065 -1400 0 1 {name=p201 sig_type=std_logic lab=vdd}
C {devices/lab_pin.sym} 1065 -1280 1 1 {name=p202 sig_type=std_logic lab=vb1}
C {devices/lab_pin.sym} 1085 -1280 1 1 {name=p203 sig_type=std_logic lab=vb2}
C {devices/lab_pin.sym} 1035 -1280 1 1 {name=p204 sig_type=std_logic lab=CLK}
C {devices/lab_pin.sym} 1035 -1400 3 1 {name=p205 sig_type=std_logic lab=L5}
C {analog/array_cell.sym} 1255 -1300 0 0 {name=x24}
C {devices/lab_pin.sym} 1325 -1400 0 1 {name=p207 sig_type=std_logic lab=vdd}
C {devices/lab_pin.sym} 1305 -1280 1 1 {name=p208 sig_type=std_logic lab=vb1}
C {devices/lab_pin.sym} 1325 -1280 1 1 {name=p209 sig_type=std_logic lab=vb2}
C {devices/lab_pin.sym} 1275 -1280 1 1 {name=p210 sig_type=std_logic lab=CLK}
C {devices/lab_pin.sym} 1275 -1400 3 1 {name=p211 sig_type=std_logic lab=L6}
C {devices/lab_pin.sym} 885 -1360 0 1 {name=p215 sig_type=std_logic lab=OUT+}
C {devices/lab_pin.sym} 1125 -1360 0 1 {name=p216 sig_type=std_logic lab=OUT+}
C {devices/lab_pin.sym} 885 -1320 0 1 {name=p217 sig_type=std_logic lab=OUT-}
C {devices/lab_pin.sym} 1125 -1320 0 1 {name=p218 sig_type=std_logic lab=OUT-}
C {devices/lab_pin.sym} 1365 -1360 0 1 {name=p219 sig_type=std_logic lab=OUT+}
C {devices/lab_pin.sym} 1365 -1320 0 1 {name=p220 sig_type=std_logic lab=OUT-}
C {analog/array_cell.sym} 1495 -1300 0 0 {name=x25}
C {devices/lab_pin.sym} 1565 -1400 0 1 {name=p222 sig_type=std_logic lab=vdd}
C {devices/lab_pin.sym} 1545 -1280 1 1 {name=p223 sig_type=std_logic lab=vb1}
C {devices/lab_pin.sym} 1565 -1280 1 1 {name=p224 sig_type=std_logic lab=vb2}
C {devices/lab_pin.sym} 1515 -1280 1 1 {name=p225 sig_type=std_logic lab=CLK}
C {devices/lab_pin.sym} 1515 -1400 3 1 {name=p226 sig_type=std_logic lab=L7}
C {devices/lab_pin.sym} 1605 -1360 0 1 {name=p228 sig_type=std_logic lab=OUT+}
C {devices/lab_pin.sym} 1605 -1320 0 1 {name=p229 sig_type=std_logic lab=OUT-}
C {analog/array_cell.sym} 1735 -1300 0 0 {name=x26}
C {devices/lab_pin.sym} 1785 -1400 0 1 {name=p231 sig_type=std_logic lab=vdd}
C {devices/lab_pin.sym} 1785 -1280 1 1 {name=p232 sig_type=std_logic lab=vb1}
C {devices/lab_pin.sym} 1805 -1280 1 1 {name=p233 sig_type=std_logic lab=vb2}
C {devices/lab_pin.sym} 1755 -1280 1 1 {name=p234 sig_type=std_logic lab=CLK}
C {devices/lab_pin.sym} 1755 -1400 3 1 {name=p235 sig_type=std_logic lab=0}
C {devices/lab_pin.sym} 1845 -1360 0 1 {name=p237 sig_type=std_logic lab=OUT+}
C {devices/lab_pin.sym} 1845 -1320 0 1 {name=p238 sig_type=std_logic lab=OUT-}
C {devices/lab_pin.sym} 35 -1135 1 0 {name=p239 sig_type=std_logic lab=H3}
C {analog/array_cell.sym} 55 -1075 0 0 {name=x27}
C {devices/lab_pin.sym} 125 -1175 0 1 {name=p240 sig_type=std_logic lab=vdd}
C {devices/lab_pin.sym} 105 -1055 1 1 {name=p241 sig_type=std_logic lab=vb1}
C {devices/lab_pin.sym} 125 -1055 1 1 {name=p242 sig_type=std_logic lab=vb2}
C {devices/lab_pin.sym} 75 -1055 1 1 {name=p243 sig_type=std_logic lab=CLK}
C {devices/lab_pin.sym} 75 -1175 3 1 {name=p244 sig_type=std_logic lab=L1}
C {analog/array_cell.sym} 295 -1075 0 0 {name=x28}
C {devices/lab_pin.sym} 365 -1175 0 1 {name=p246 sig_type=std_logic lab=vdd}
C {devices/lab_pin.sym} 345 -1055 1 1 {name=p247 sig_type=std_logic lab=vb1}
C {devices/lab_pin.sym} 365 -1055 1 1 {name=p248 sig_type=std_logic lab=vb2}
C {devices/lab_pin.sym} 315 -1055 1 1 {name=p249 sig_type=std_logic lab=CLK}
C {devices/lab_pin.sym} 315 -1175 3 1 {name=p250 sig_type=std_logic lab=L2}
C {analog/array_cell.sym} 535 -1075 0 0 {name=x29}
C {devices/lab_pin.sym} 585 -1175 0 1 {name=p252 sig_type=std_logic lab=vdd}
C {devices/lab_pin.sym} 585 -1055 1 1 {name=p253 sig_type=std_logic lab=vb1}
C {devices/lab_pin.sym} 605 -1055 1 1 {name=p254 sig_type=std_logic lab=vb2}
C {devices/lab_pin.sym} 555 -1055 1 1 {name=p255 sig_type=std_logic lab=CLK}
C {devices/lab_pin.sym} 555 -1175 3 1 {name=p256 sig_type=std_logic lab=L3}
C {devices/lab_pin.sym} 35 -1095 2 1 {name=p257 sig_type=std_logic lab=H4}
C {devices/lab_pin.sym} 165 -1135 0 1 {name=p260 sig_type=std_logic lab=OUT+}
C {devices/lab_pin.sym} 405 -1135 0 1 {name=p261 sig_type=std_logic lab=OUT+}
C {devices/lab_pin.sym} 165 -1095 0 1 {name=p262 sig_type=std_logic lab=OUT-}
C {devices/lab_pin.sym} 405 -1095 0 1 {name=p263 sig_type=std_logic lab=OUT-}
C {devices/lab_pin.sym} 645 -1135 0 1 {name=p264 sig_type=std_logic lab=OUT+}
C {devices/lab_pin.sym} 645 -1095 0 1 {name=p265 sig_type=std_logic lab=OUT-}
C {analog/array_cell.sym} 775 -1075 0 0 {name=x30}
C {devices/lab_pin.sym} 825 -1175 0 1 {name=p267 sig_type=std_logic lab=vdd}
C {devices/lab_pin.sym} 825 -1055 1 1 {name=p268 sig_type=std_logic lab=vb1}
C {devices/lab_pin.sym} 845 -1055 1 1 {name=p269 sig_type=std_logic lab=vb2}
C {devices/lab_pin.sym} 795 -1055 1 1 {name=p270 sig_type=std_logic lab=CLK}
C {devices/lab_pin.sym} 795 -1175 3 1 {name=p271 sig_type=std_logic lab=L4}
C {analog/array_cell.sym} 1015 -1075 0 0 {name=x31}
C {devices/lab_pin.sym} 1065 -1175 0 1 {name=p273 sig_type=std_logic lab=vdd}
C {devices/lab_pin.sym} 1065 -1055 1 1 {name=p274 sig_type=std_logic lab=vb1}
C {devices/lab_pin.sym} 1085 -1055 1 1 {name=p275 sig_type=std_logic lab=vb2}
C {devices/lab_pin.sym} 1035 -1055 1 1 {name=p276 sig_type=std_logic lab=CLK}
C {devices/lab_pin.sym} 1035 -1175 3 1 {name=p277 sig_type=std_logic lab=L5}
C {analog/array_cell.sym} 1255 -1075 0 0 {name=x32}
C {devices/lab_pin.sym} 1305 -1175 0 1 {name=p279 sig_type=std_logic lab=vdd}
C {devices/lab_pin.sym} 1305 -1055 1 1 {name=p280 sig_type=std_logic lab=vb1}
C {devices/lab_pin.sym} 1325 -1055 1 1 {name=p281 sig_type=std_logic lab=vb2}
C {devices/lab_pin.sym} 1275 -1055 1 1 {name=p282 sig_type=std_logic lab=CLK}
C {devices/lab_pin.sym} 1275 -1175 3 1 {name=p283 sig_type=std_logic lab=L6}
C {devices/lab_pin.sym} 885 -1135 0 1 {name=p287 sig_type=std_logic lab=OUT+}
C {devices/lab_pin.sym} 1125 -1135 0 1 {name=p288 sig_type=std_logic lab=OUT+}
C {devices/lab_pin.sym} 885 -1095 0 1 {name=p289 sig_type=std_logic lab=OUT-}
C {devices/lab_pin.sym} 1125 -1095 0 1 {name=p290 sig_type=std_logic lab=OUT-}
C {devices/lab_pin.sym} 1365 -1135 0 1 {name=p291 sig_type=std_logic lab=OUT+}
C {devices/lab_pin.sym} 1365 -1095 0 1 {name=p292 sig_type=std_logic lab=OUT-}
C {analog/array_cell.sym} 1495 -1075 0 0 {name=x33}
C {devices/lab_pin.sym} 1545 -1175 0 1 {name=p294 sig_type=std_logic lab=vdd}
C {devices/lab_pin.sym} 1545 -1055 1 1 {name=p295 sig_type=std_logic lab=vb1}
C {devices/lab_pin.sym} 1565 -1055 1 1 {name=p296 sig_type=std_logic lab=vb2}
C {devices/lab_pin.sym} 1515 -1055 1 1 {name=p297 sig_type=std_logic lab=CLK}
C {devices/lab_pin.sym} 1515 -1175 3 1 {name=p298 sig_type=std_logic lab=L7}
C {devices/lab_pin.sym} 1605 -1135 0 1 {name=p300 sig_type=std_logic lab=OUT+}
C {devices/lab_pin.sym} 1605 -1095 0 1 {name=p301 sig_type=std_logic lab=OUT-}
C {analog/array_cell.sym} 1735 -1075 0 0 {name=x34}
C {devices/lab_pin.sym} 1785 -1175 0 1 {name=p303 sig_type=std_logic lab=vdd}
C {devices/lab_pin.sym} 1785 -1055 1 1 {name=p304 sig_type=std_logic lab=vb1}
C {devices/lab_pin.sym} 1805 -1055 1 1 {name=p305 sig_type=std_logic lab=vb2}
C {devices/lab_pin.sym} 1755 -1055 1 1 {name=p306 sig_type=std_logic lab=CLK}
C {devices/lab_pin.sym} 1755 -1175 3 1 {name=p307 sig_type=std_logic lab=0}
C {devices/lab_pin.sym} 1845 -1135 0 1 {name=p309 sig_type=std_logic lab=OUT+}
C {devices/lab_pin.sym} 1845 -1095 0 1 {name=p310 sig_type=std_logic lab=OUT-}
C {devices/lab_pin.sym} 275 -1360 1 0 {name=p173 sig_type=std_logic lab=H2}
C {devices/lab_pin.sym} 275 -1320 2 1 {name=p186 sig_type=std_logic lab=H3}
C {devices/lab_pin.sym} 515 -1360 1 0 {name=p179 sig_type=std_logic lab=H2}
C {devices/lab_pin.sym} 515 -1320 2 1 {name=p187 sig_type=std_logic lab=H3}
C {devices/lab_pin.sym} 755 -1360 1 0 {name=p194 sig_type=std_logic lab=H2}
C {devices/lab_pin.sym} 755 -1320 2 1 {name=p200 sig_type=std_logic lab=H3}
C {devices/lab_pin.sym} 995 -1360 1 0 {name=p206 sig_type=std_logic lab=H2}
C {devices/lab_pin.sym} 995 -1320 2 1 {name=p212 sig_type=std_logic lab=H3}
C {devices/lab_pin.sym} 1235 -1360 1 0 {name=p213 sig_type=std_logic lab=H2}
C {devices/lab_pin.sym} 1235 -1320 2 1 {name=p214 sig_type=std_logic lab=H3}
C {devices/lab_pin.sym} 1475 -1360 1 0 {name=p221 sig_type=std_logic lab=H2}
C {devices/lab_pin.sym} 1475 -1320 2 1 {name=p227 sig_type=std_logic lab=H3}
C {devices/lab_pin.sym} 1715 -1350 1 0 {name=p230 sig_type=std_logic lab=H2}
C {devices/lab_pin.sym} 1715 -1330 2 1 {name=p236 sig_type=std_logic lab=H3}
C {devices/lab_pin.sym} 275 -1135 1 0 {name=p245 sig_type=std_logic lab=H3}
C {devices/lab_pin.sym} 275 -1095 2 1 {name=p251 sig_type=std_logic lab=H4}
C {devices/lab_pin.sym} 515 -1135 1 0 {name=p258 sig_type=std_logic lab=H3}
C {devices/lab_pin.sym} 515 -1095 2 1 {name=p259 sig_type=std_logic lab=H4}
C {devices/lab_pin.sym} 755 -1135 1 0 {name=p266 sig_type=std_logic lab=H3}
C {devices/lab_pin.sym} 755 -1095 2 1 {name=p272 sig_type=std_logic lab=H4}
C {devices/lab_pin.sym} 995 -1135 1 0 {name=p278 sig_type=std_logic lab=H3}
C {devices/lab_pin.sym} 995 -1095 2 1 {name=p284 sig_type=std_logic lab=H4}
C {devices/lab_pin.sym} 1235 -1135 1 0 {name=p285 sig_type=std_logic lab=H3}
C {devices/lab_pin.sym} 1235 -1095 2 1 {name=p286 sig_type=std_logic lab=H4}
C {devices/lab_pin.sym} 1475 -1135 1 0 {name=p293 sig_type=std_logic lab=H3}
C {devices/lab_pin.sym} 1475 -1095 2 1 {name=p299 sig_type=std_logic lab=H4}
C {devices/lab_pin.sym} 1715 -1135 1 0 {name=p302 sig_type=std_logic lab=H3}
C {devices/lab_pin.sym} 1715 -1095 2 1 {name=p308 sig_type=std_logic lab=H4}
C {devices/lab_pin.sym} 45 -905 1 0 {name=p311 sig_type=std_logic lab=H4}
C {analog/array_cell.sym} 65 -845 0 0 {name=x35}
C {devices/lab_pin.sym} 115 -945 0 1 {name=p312 sig_type=std_logic lab=vdd}
C {devices/lab_pin.sym} 115 -825 1 1 {name=p313 sig_type=std_logic lab=vb1}
C {devices/lab_pin.sym} 135 -825 1 1 {name=p314 sig_type=std_logic lab=vb2}
C {devices/lab_pin.sym} 85 -825 1 1 {name=p315 sig_type=std_logic lab=CLK}
C {devices/lab_pin.sym} 85 -945 3 1 {name=p316 sig_type=std_logic lab=L1}
C {analog/array_cell.sym} 295 -850 0 0 {name=x36}
C {devices/lab_pin.sym} 345 -950 0 1 {name=p318 sig_type=std_logic lab=vdd}
C {devices/lab_pin.sym} 345 -830 1 1 {name=p319 sig_type=std_logic lab=vb1}
C {devices/lab_pin.sym} 365 -830 1 1 {name=p320 sig_type=std_logic lab=vb2}
C {devices/lab_pin.sym} 315 -830 1 1 {name=p321 sig_type=std_logic lab=CLK}
C {devices/lab_pin.sym} 315 -950 3 1 {name=p322 sig_type=std_logic lab=L2}
C {analog/array_cell.sym} 535 -850 0 0 {name=x37}
C {devices/lab_pin.sym} 585 -950 0 1 {name=p324 sig_type=std_logic lab=vdd}
C {devices/lab_pin.sym} 585 -830 1 1 {name=p325 sig_type=std_logic lab=vb1}
C {devices/lab_pin.sym} 605 -830 1 1 {name=p326 sig_type=std_logic lab=vb2}
C {devices/lab_pin.sym} 555 -830 1 1 {name=p327 sig_type=std_logic lab=CLK}
C {devices/lab_pin.sym} 555 -950 3 1 {name=p328 sig_type=std_logic lab=L3}
C {devices/lab_pin.sym} 45 -865 2 1 {name=p329 sig_type=std_logic lab=H5}
C {devices/lab_pin.sym} 175 -905 3 1 {name=p332 sig_type=std_logic lab=OUT+}
C {devices/lab_pin.sym} 405 -910 0 1 {name=p333 sig_type=std_logic lab=OUT+}
C {devices/lab_pin.sym} 175 -865 1 1 {name=p334 sig_type=std_logic lab=OUT-}
C {devices/lab_pin.sym} 405 -870 0 1 {name=p335 sig_type=std_logic lab=OUT-}
C {devices/lab_pin.sym} 645 -910 0 1 {name=p336 sig_type=std_logic lab=OUT+}
C {devices/lab_pin.sym} 645 -870 0 1 {name=p337 sig_type=std_logic lab=OUT-}
C {analog/array_cell.sym} 775 -850 0 0 {name=x38}
C {devices/lab_pin.sym} 825 -950 0 1 {name=p339 sig_type=std_logic lab=vdd}
C {devices/lab_pin.sym} 825 -830 1 1 {name=p340 sig_type=std_logic lab=vb1}
C {devices/lab_pin.sym} 845 -830 1 1 {name=p341 sig_type=std_logic lab=vb2}
C {devices/lab_pin.sym} 795 -830 1 1 {name=p342 sig_type=std_logic lab=CLK}
C {devices/lab_pin.sym} 795 -950 3 1 {name=p343 sig_type=std_logic lab=L4}
C {analog/array_cell.sym} 1015 -850 0 0 {name=x39}
C {devices/lab_pin.sym} 1065 -950 0 1 {name=p345 sig_type=std_logic lab=vdd}
C {devices/lab_pin.sym} 1065 -830 1 1 {name=p346 sig_type=std_logic lab=vb1}
C {devices/lab_pin.sym} 1085 -830 1 1 {name=p347 sig_type=std_logic lab=vb2}
C {devices/lab_pin.sym} 1035 -830 1 1 {name=p348 sig_type=std_logic lab=CLK}
C {devices/lab_pin.sym} 1035 -950 3 1 {name=p349 sig_type=std_logic lab=L5}
C {analog/array_cell.sym} 1255 -850 0 0 {name=x40}
C {devices/lab_pin.sym} 1305 -950 0 1 {name=p351 sig_type=std_logic lab=vdd}
C {devices/lab_pin.sym} 1305 -830 1 1 {name=p352 sig_type=std_logic lab=vb1}
C {devices/lab_pin.sym} 1325 -830 1 1 {name=p353 sig_type=std_logic lab=vb2}
C {devices/lab_pin.sym} 1275 -830 1 1 {name=p354 sig_type=std_logic lab=CLK}
C {devices/lab_pin.sym} 1275 -950 3 1 {name=p355 sig_type=std_logic lab=L6}
C {devices/lab_pin.sym} 885 -910 0 1 {name=p359 sig_type=std_logic lab=OUT+}
C {devices/lab_pin.sym} 1125 -910 0 1 {name=p360 sig_type=std_logic lab=OUT+}
C {devices/lab_pin.sym} 885 -870 0 1 {name=p361 sig_type=std_logic lab=OUT-}
C {devices/lab_pin.sym} 1125 -870 0 1 {name=p362 sig_type=std_logic lab=OUT-}
C {devices/lab_pin.sym} 1365 -910 0 1 {name=p363 sig_type=std_logic lab=OUT+}
C {devices/lab_pin.sym} 1365 -870 0 1 {name=p364 sig_type=std_logic lab=OUT-}
C {analog/array_cell.sym} 1495 -850 0 0 {name=x41}
C {devices/lab_pin.sym} 1545 -950 0 1 {name=p366 sig_type=std_logic lab=vdd}
C {devices/lab_pin.sym} 1545 -830 1 1 {name=p367 sig_type=std_logic lab=vb1}
C {devices/lab_pin.sym} 1565 -830 1 1 {name=p368 sig_type=std_logic lab=vb2}
C {devices/lab_pin.sym} 1515 -830 1 1 {name=p369 sig_type=std_logic lab=CLK}
C {devices/lab_pin.sym} 1515 -950 3 1 {name=p370 sig_type=std_logic lab=L7}
C {devices/lab_pin.sym} 1605 -910 0 1 {name=p372 sig_type=std_logic lab=OUT+}
C {devices/lab_pin.sym} 1605 -870 0 1 {name=p373 sig_type=std_logic lab=OUT-}
C {analog/array_cell.sym} 1735 -850 0 0 {name=x42}
C {devices/lab_pin.sym} 1785 -950 0 1 {name=p375 sig_type=std_logic lab=vdd}
C {devices/lab_pin.sym} 1785 -830 1 1 {name=p376 sig_type=std_logic lab=vb1}
C {devices/lab_pin.sym} 1805 -830 1 1 {name=p377 sig_type=std_logic lab=vb2}
C {devices/lab_pin.sym} 1755 -830 1 1 {name=p378 sig_type=std_logic lab=CLK}
C {devices/lab_pin.sym} 1755 -950 3 1 {name=p379 sig_type=std_logic lab=0}
C {devices/lab_pin.sym} 1845 -910 0 1 {name=p381 sig_type=std_logic lab=OUT+}
C {devices/lab_pin.sym} 1845 -870 0 1 {name=p382 sig_type=std_logic lab=OUT-}
C {devices/lab_pin.sym} 35 -685 1 0 {name=p383 sig_type=std_logic lab=H5}
C {analog/array_cell.sym} 55 -625 0 0 {name=x43}
C {devices/lab_pin.sym} 105 -725 0 1 {name=p384 sig_type=std_logic lab=vdd}
C {devices/lab_pin.sym} 105 -605 1 1 {name=p385 sig_type=std_logic lab=vb1}
C {devices/lab_pin.sym} 125 -605 1 1 {name=p386 sig_type=std_logic lab=vb2}
C {devices/lab_pin.sym} 75 -605 1 1 {name=p387 sig_type=std_logic lab=CLK}
C {devices/lab_pin.sym} 75 -725 3 1 {name=p388 sig_type=std_logic lab=L1}
C {analog/array_cell.sym} 295 -625 0 0 {name=x44}
C {devices/lab_pin.sym} 345 -725 0 1 {name=p390 sig_type=std_logic lab=vdd}
C {devices/lab_pin.sym} 345 -605 1 1 {name=p391 sig_type=std_logic lab=vb1}
C {devices/lab_pin.sym} 365 -605 1 1 {name=p392 sig_type=std_logic lab=vb2}
C {devices/lab_pin.sym} 315 -605 1 1 {name=p393 sig_type=std_logic lab=CLK}
C {devices/lab_pin.sym} 315 -725 3 1 {name=p394 sig_type=std_logic lab=L2}
C {analog/array_cell.sym} 535 -625 0 0 {name=x45}
C {devices/lab_pin.sym} 585 -725 0 1 {name=p396 sig_type=std_logic lab=vdd}
C {devices/lab_pin.sym} 585 -605 1 1 {name=p397 sig_type=std_logic lab=vb1}
C {devices/lab_pin.sym} 605 -605 1 1 {name=p398 sig_type=std_logic lab=vb2}
C {devices/lab_pin.sym} 565 -605 1 1 {name=p399 sig_type=std_logic lab=CLK}
C {devices/lab_pin.sym} 555 -725 3 1 {name=p400 sig_type=std_logic lab=L3}
C {devices/lab_pin.sym} 35 -645 2 1 {name=p401 sig_type=std_logic lab=H6}
C {devices/lab_pin.sym} 165 -685 0 1 {name=p404 sig_type=std_logic lab=OUT+}
C {devices/lab_pin.sym} 405 -685 0 1 {name=p405 sig_type=std_logic lab=OUT+}
C {devices/lab_pin.sym} 165 -645 0 1 {name=p406 sig_type=std_logic lab=OUT-}
C {devices/lab_pin.sym} 405 -645 0 1 {name=p407 sig_type=std_logic lab=OUT-}
C {devices/lab_pin.sym} 645 -685 0 1 {name=p408 sig_type=std_logic lab=OUT+}
C {devices/lab_pin.sym} 645 -645 0 1 {name=p409 sig_type=std_logic lab=OUT-}
C {analog/array_cell.sym} 775 -625 0 0 {name=x46}
C {devices/lab_pin.sym} 825 -725 0 1 {name=p411 sig_type=std_logic lab=vdd}
C {devices/lab_pin.sym} 825 -605 1 1 {name=p412 sig_type=std_logic lab=vb1}
C {devices/lab_pin.sym} 845 -605 1 1 {name=p413 sig_type=std_logic lab=vb2}
C {devices/lab_pin.sym} 795 -605 1 1 {name=p414 sig_type=std_logic lab=CLK}
C {devices/lab_pin.sym} 795 -725 3 1 {name=p415 sig_type=std_logic lab=L4}
C {analog/array_cell.sym} 1015 -625 0 0 {name=x47}
C {devices/lab_pin.sym} 1065 -725 0 1 {name=p417 sig_type=std_logic lab=vdd}
C {devices/lab_pin.sym} 1065 -605 1 1 {name=p418 sig_type=std_logic lab=vb1}
C {devices/lab_pin.sym} 1085 -605 1 1 {name=p419 sig_type=std_logic lab=vb2}
C {devices/lab_pin.sym} 1035 -605 1 1 {name=p420 sig_type=std_logic lab=CLK}
C {devices/lab_pin.sym} 1035 -725 3 1 {name=p421 sig_type=std_logic lab=L5}
C {analog/array_cell.sym} 1255 -625 0 0 {name=x48}
C {devices/lab_pin.sym} 1305 -725 0 1 {name=p423 sig_type=std_logic lab=vdd}
C {devices/lab_pin.sym} 1305 -605 1 1 {name=p424 sig_type=std_logic lab=vb1}
C {devices/lab_pin.sym} 1325 -605 1 1 {name=p425 sig_type=std_logic lab=vb2}
C {devices/lab_pin.sym} 1275 -605 1 1 {name=p426 sig_type=std_logic lab=CLK}
C {devices/lab_pin.sym} 1275 -725 3 1 {name=p427 sig_type=std_logic lab=L6}
C {devices/lab_pin.sym} 885 -685 0 1 {name=p431 sig_type=std_logic lab=OUT+}
C {devices/lab_pin.sym} 1125 -685 0 1 {name=p432 sig_type=std_logic lab=OUT+}
C {devices/lab_pin.sym} 885 -645 0 1 {name=p433 sig_type=std_logic lab=OUT-}
C {devices/lab_pin.sym} 1125 -645 0 1 {name=p434 sig_type=std_logic lab=OUT-}
C {devices/lab_pin.sym} 1365 -685 0 1 {name=p435 sig_type=std_logic lab=OUT+}
C {devices/lab_pin.sym} 1365 -645 0 1 {name=p436 sig_type=std_logic lab=OUT-}
C {analog/array_cell.sym} 1495 -625 0 0 {name=x49}
C {devices/lab_pin.sym} 1545 -725 0 1 {name=p438 sig_type=std_logic lab=vdd}
C {devices/lab_pin.sym} 1545 -605 1 1 {name=p439 sig_type=std_logic lab=vb1}
C {devices/lab_pin.sym} 1565 -605 1 1 {name=p440 sig_type=std_logic lab=vb2}
C {devices/lab_pin.sym} 1515 -605 1 1 {name=p441 sig_type=std_logic lab=CLK}
C {devices/lab_pin.sym} 1515 -725 3 1 {name=p442 sig_type=std_logic lab=L7}
C {devices/lab_pin.sym} 1605 -685 0 1 {name=p444 sig_type=std_logic lab=OUT+}
C {devices/lab_pin.sym} 1605 -645 0 1 {name=p445 sig_type=std_logic lab=OUT-}
C {analog/array_cell.sym} 1735 -625 0 0 {name=x50}
C {devices/lab_pin.sym} 1785 -725 0 1 {name=p447 sig_type=std_logic lab=vdd}
C {devices/lab_pin.sym} 1785 -605 1 1 {name=p448 sig_type=std_logic lab=vb1}
C {devices/lab_pin.sym} 1805 -605 1 1 {name=p449 sig_type=std_logic lab=vb2}
C {devices/lab_pin.sym} 1755 -605 1 1 {name=p450 sig_type=std_logic lab=CLK}
C {devices/lab_pin.sym} 1755 -725 3 1 {name=p451 sig_type=std_logic lab=0}
C {devices/lab_pin.sym} 1845 -685 0 1 {name=p453 sig_type=std_logic lab=OUT+}
C {devices/lab_pin.sym} 1845 -645 0 1 {name=p454 sig_type=std_logic lab=OUT-}
C {analog/array_cell.sym} 55 -400 0 0 {name=x51}
C {devices/lab_pin.sym} 105 -500 0 1 {name=p456 sig_type=std_logic lab=vdd}
C {devices/lab_pin.sym} 105 -380 1 1 {name=p457 sig_type=std_logic lab=vb1}
C {devices/lab_pin.sym} 125 -380 1 1 {name=p458 sig_type=std_logic lab=vb2}
C {devices/lab_pin.sym} 75 -380 1 1 {name=p459 sig_type=std_logic lab=CLK}
C {devices/lab_pin.sym} 75 -500 3 1 {name=p460 sig_type=std_logic lab=L1}
C {analog/array_cell.sym} 295 -400 0 0 {name=x52}
C {devices/lab_pin.sym} 365 -500 0 1 {name=p461 sig_type=std_logic lab=vdd}
C {devices/lab_pin.sym} 345 -380 1 1 {name=p462 sig_type=std_logic lab=vb1}
C {devices/lab_pin.sym} 365 -380 1 1 {name=p463 sig_type=std_logic lab=vb2}
C {devices/lab_pin.sym} 315 -380 1 1 {name=p464 sig_type=std_logic lab=CLK}
C {devices/lab_pin.sym} 315 -500 3 1 {name=p465 sig_type=std_logic lab=L2}
C {analog/array_cell.sym} 535 -400 0 0 {name=x53}
C {devices/lab_pin.sym} 605 -500 0 1 {name=p466 sig_type=std_logic lab=vdd}
C {devices/lab_pin.sym} 585 -380 1 1 {name=p467 sig_type=std_logic lab=vb1}
C {devices/lab_pin.sym} 605 -380 1 1 {name=p468 sig_type=std_logic lab=vb2}
C {devices/lab_pin.sym} 555 -380 1 1 {name=p469 sig_type=std_logic lab=CLK}
C {devices/lab_pin.sym} 555 -500 3 1 {name=p470 sig_type=std_logic lab=L3}
C {devices/lab_pin.sym} 165 -460 0 1 {name=p472 sig_type=std_logic lab=OUT+}
C {devices/lab_pin.sym} 415 -450 0 1 {name=p473 sig_type=std_logic lab=OUT+}
C {devices/lab_pin.sym} 165 -420 0 1 {name=p474 sig_type=std_logic lab=OUT-}
C {devices/lab_pin.sym} 415 -430 0 1 {name=p475 sig_type=std_logic lab=OUT-}
C {devices/lab_pin.sym} 655 -450 0 1 {name=p476 sig_type=std_logic lab=OUT+}
C {devices/lab_pin.sym} 655 -430 0 1 {name=p477 sig_type=std_logic lab=OUT-}
C {analog/array_cell.sym} 775 -400 0 0 {name=x54}
C {devices/lab_pin.sym} 845 -500 0 1 {name=p478 sig_type=std_logic lab=vdd}
C {devices/lab_pin.sym} 825 -380 1 1 {name=p479 sig_type=std_logic lab=vb1}
C {devices/lab_pin.sym} 845 -380 1 1 {name=p480 sig_type=std_logic lab=vb2}
C {devices/lab_pin.sym} 795 -380 1 1 {name=p481 sig_type=std_logic lab=CLK}
C {devices/lab_pin.sym} 795 -500 3 1 {name=p482 sig_type=std_logic lab=L4}
C {analog/array_cell.sym} 1015 -400 0 0 {name=x55}
C {devices/lab_pin.sym} 1085 -500 0 1 {name=p483 sig_type=std_logic lab=vdd}
C {devices/lab_pin.sym} 1065 -380 1 1 {name=p484 sig_type=std_logic lab=vb1}
C {devices/lab_pin.sym} 1085 -380 1 1 {name=p485 sig_type=std_logic lab=vb2}
C {devices/lab_pin.sym} 1035 -380 1 1 {name=p486 sig_type=std_logic lab=CLK}
C {devices/lab_pin.sym} 1035 -500 3 1 {name=p487 sig_type=std_logic lab=L5}
C {analog/array_cell.sym} 1255 -400 0 0 {name=x56}
C {devices/lab_pin.sym} 1325 -500 0 1 {name=p488 sig_type=std_logic lab=vdd}
C {devices/lab_pin.sym} 1305 -380 1 1 {name=p489 sig_type=std_logic lab=vb1}
C {devices/lab_pin.sym} 1325 -380 1 1 {name=p490 sig_type=std_logic lab=vb2}
C {devices/lab_pin.sym} 1275 -380 1 1 {name=p491 sig_type=std_logic lab=CLK}
C {devices/lab_pin.sym} 1275 -500 3 1 {name=p492 sig_type=std_logic lab=L6}
C {devices/lab_pin.sym} 895 -450 0 1 {name=p493 sig_type=std_logic lab=OUT+}
C {devices/lab_pin.sym} 1135 -450 0 1 {name=p494 sig_type=std_logic lab=OUT+}
C {devices/lab_pin.sym} 895 -430 0 1 {name=p495 sig_type=std_logic lab=OUT-}
C {devices/lab_pin.sym} 1135 -430 0 1 {name=p496 sig_type=std_logic lab=OUT-}
C {devices/lab_pin.sym} 1375 -450 0 1 {name=p497 sig_type=std_logic lab=OUT+}
C {devices/lab_pin.sym} 1375 -430 0 1 {name=p498 sig_type=std_logic lab=OUT-}
C {analog/array_cell.sym} 1495 -400 0 0 {name=x57}
C {devices/lab_pin.sym} 1565 -500 0 1 {name=p499 sig_type=std_logic lab=vdd}
C {devices/lab_pin.sym} 1545 -380 1 1 {name=p500 sig_type=std_logic lab=vb1}
C {devices/lab_pin.sym} 1565 -380 1 1 {name=p501 sig_type=std_logic lab=vb2}
C {devices/lab_pin.sym} 1515 -380 1 1 {name=p502 sig_type=std_logic lab=CLK}
C {devices/lab_pin.sym} 1515 -500 3 1 {name=p503 sig_type=std_logic lab=L7}
C {devices/lab_pin.sym} 1615 -450 0 1 {name=p504 sig_type=std_logic lab=OUT+}
C {devices/lab_pin.sym} 1615 -430 0 1 {name=p505 sig_type=std_logic lab=OUT-}
C {analog/array_cell.sym} 1735 -400 0 0 {name=x58}
C {devices/lab_pin.sym} 1785 -500 0 1 {name=p506 sig_type=std_logic lab=vdd}
C {devices/lab_pin.sym} 1785 -380 1 1 {name=p507 sig_type=std_logic lab=vb1}
C {devices/lab_pin.sym} 1805 -380 1 1 {name=p508 sig_type=std_logic lab=vb2}
C {devices/lab_pin.sym} 1755 -380 1 1 {name=p509 sig_type=std_logic lab=CLK}
C {devices/lab_pin.sym} 1755 -500 3 1 {name=p510 sig_type=std_logic lab=0}
C {devices/lab_pin.sym} 1845 -460 0 1 {name=p511 sig_type=std_logic lab=OUT+}
C {devices/lab_pin.sym} 1845 -420 0 1 {name=p512 sig_type=std_logic lab=OUT-}
C {devices/lab_pin.sym} 35 -235 1 0 {name=p513 sig_type=std_logic lab=H7}
C {analog/array_cell.sym} 55 -175 0 0 {name=x59}
C {devices/lab_pin.sym} 105 -275 0 1 {name=p514 sig_type=std_logic lab=vdd}
C {devices/lab_pin.sym} 105 -155 1 1 {name=p515 sig_type=std_logic lab=vb1}
C {devices/lab_pin.sym} 125 -155 1 1 {name=p516 sig_type=std_logic lab=vb2}
C {devices/lab_pin.sym} 75 -155 1 1 {name=p517 sig_type=std_logic lab=CLK}
C {devices/lab_pin.sym} 75 -275 3 1 {name=p518 sig_type=std_logic lab=L1}
C {analog/array_cell.sym} 295 -175 0 0 {name=x60}
C {devices/lab_pin.sym} 345 -275 0 1 {name=p519 sig_type=std_logic lab=vdd}
C {devices/lab_pin.sym} 345 -155 1 1 {name=p520 sig_type=std_logic lab=vb1}
C {devices/lab_pin.sym} 365 -155 1 1 {name=p521 sig_type=std_logic lab=vb2}
C {devices/lab_pin.sym} 315 -155 1 1 {name=p522 sig_type=std_logic lab=CLK}
C {devices/lab_pin.sym} 315 -275 3 1 {name=p523 sig_type=std_logic lab=L2}
C {analog/array_cell.sym} 535 -175 0 0 {name=x61}
C {devices/lab_pin.sym} 585 -275 0 1 {name=p524 sig_type=std_logic lab=vdd}
C {devices/lab_pin.sym} 585 -155 1 1 {name=p525 sig_type=std_logic lab=vb1}
C {devices/lab_pin.sym} 605 -155 1 1 {name=p526 sig_type=std_logic lab=vb2}
C {devices/lab_pin.sym} 555 -155 1 1 {name=p527 sig_type=std_logic lab=CLK}
C {devices/lab_pin.sym} 555 -275 3 1 {name=p528 sig_type=std_logic lab=L3}
C {devices/lab_pin.sym} 35 -195 2 1 {name=p529 sig_type=std_logic lab=0}
C {devices/lab_pin.sym} 165 -235 0 1 {name=p530 sig_type=std_logic lab=OUT+}
C {devices/lab_pin.sym} 405 -235 0 1 {name=p531 sig_type=std_logic lab=OUT+}
C {devices/lab_pin.sym} 165 -195 0 1 {name=p532 sig_type=std_logic lab=OUT-}
C {devices/lab_pin.sym} 405 -195 0 1 {name=p533 sig_type=std_logic lab=OUT-}
C {devices/lab_pin.sym} 645 -235 0 1 {name=p534 sig_type=std_logic lab=OUT+}
C {devices/lab_pin.sym} 645 -195 0 1 {name=p535 sig_type=std_logic lab=OUT-}
C {analog/array_cell.sym} 775 -175 0 0 {name=x62}
C {devices/lab_pin.sym} 825 -275 0 1 {name=p536 sig_type=std_logic lab=vdd}
C {devices/lab_pin.sym} 825 -155 1 1 {name=p537 sig_type=std_logic lab=vb1}
C {devices/lab_pin.sym} 845 -155 1 1 {name=p538 sig_type=std_logic lab=vb2}
C {devices/lab_pin.sym} 795 -155 1 1 {name=p539 sig_type=std_logic lab=CLK}
C {devices/lab_pin.sym} 795 -275 3 1 {name=p540 sig_type=std_logic lab=L4}
C {analog/array_cell.sym} 1015 -175 0 0 {name=x63}
C {devices/lab_pin.sym} 1065 -275 0 1 {name=p541 sig_type=std_logic lab=vdd}
C {devices/lab_pin.sym} 1065 -155 1 1 {name=p542 sig_type=std_logic lab=vb1}
C {devices/lab_pin.sym} 1085 -155 1 1 {name=p543 sig_type=std_logic lab=vb2}
C {devices/lab_pin.sym} 1035 -155 1 1 {name=p544 sig_type=std_logic lab=CLK}
C {devices/lab_pin.sym} 1035 -275 3 1 {name=p545 sig_type=std_logic lab=L5}
C {analog/array_cell.sym} 1255 -175 0 0 {name=x64}
C {devices/lab_pin.sym} 1305 -275 0 1 {name=p546 sig_type=std_logic lab=vdd}
C {devices/lab_pin.sym} 1305 -155 1 1 {name=p547 sig_type=std_logic lab=vb1}
C {devices/lab_pin.sym} 1325 -155 1 1 {name=p548 sig_type=std_logic lab=vb2}
C {devices/lab_pin.sym} 1275 -155 1 1 {name=p549 sig_type=std_logic lab=CLK}
C {devices/lab_pin.sym} 1275 -275 3 1 {name=p550 sig_type=std_logic lab=L6}
C {devices/lab_pin.sym} 885 -235 0 1 {name=p551 sig_type=std_logic lab=OUT+}
C {devices/lab_pin.sym} 1125 -235 0 1 {name=p552 sig_type=std_logic lab=OUT+}
C {devices/lab_pin.sym} 885 -195 0 1 {name=p553 sig_type=std_logic lab=OUT-}
C {devices/lab_pin.sym} 1125 -195 0 1 {name=p554 sig_type=std_logic lab=OUT-}
C {devices/lab_pin.sym} 1365 -235 0 1 {name=p555 sig_type=std_logic lab=OUT+}
C {devices/lab_pin.sym} 1365 -195 0 1 {name=p556 sig_type=std_logic lab=OUT-}
C {analog/array_cell.sym} 1495 -175 0 0 {name=x65}
C {devices/lab_pin.sym} 1545 -275 0 1 {name=p557 sig_type=std_logic lab=vdd}
C {devices/lab_pin.sym} 1545 -155 1 1 {name=p558 sig_type=std_logic lab=vb1}
C {devices/lab_pin.sym} 1565 -155 1 1 {name=p559 sig_type=std_logic lab=vb2}
C {devices/lab_pin.sym} 1515 -155 1 1 {name=p560 sig_type=std_logic lab=CLK}
C {devices/lab_pin.sym} 1515 -275 3 1 {name=p561 sig_type=std_logic lab=L7}
C {devices/lab_pin.sym} 1605 -235 0 1 {name=p562 sig_type=std_logic lab=OUT+}
C {devices/lab_pin.sym} 1605 -195 0 1 {name=p563 sig_type=std_logic lab=OUT-}
C {analog/array_cell.sym} 1735 -175 0 0 {name=x66}
C {devices/lab_pin.sym} 1785 -275 0 1 {name=p564 sig_type=std_logic lab=vdd}
C {devices/lab_pin.sym} 1785 -155 1 1 {name=p565 sig_type=std_logic lab=vb1}
C {devices/lab_pin.sym} 1805 -155 1 1 {name=p566 sig_type=std_logic lab=vb2}
C {devices/lab_pin.sym} 1755 -155 1 1 {name=p567 sig_type=std_logic lab=CLK}
C {devices/lab_pin.sym} 1755 -275 3 1 {name=p568 sig_type=std_logic lab=0}
C {devices/lab_pin.sym} 1845 -235 0 1 {name=p569 sig_type=std_logic lab=OUT+}
C {devices/lab_pin.sym} 1845 -195 0 1 {name=p570 sig_type=std_logic lab=OUT-}
C {devices/lab_pin.sym} 275 -910 1 0 {name=p317 sig_type=std_logic lab=H4}
C {devices/lab_pin.sym} 275 -870 2 1 {name=p323 sig_type=std_logic lab=H5}
C {devices/lab_pin.sym} 515 -910 1 0 {name=p330 sig_type=std_logic lab=H4}
C {devices/lab_pin.sym} 515 -870 2 1 {name=p331 sig_type=std_logic lab=H5}
C {devices/lab_pin.sym} 755 -910 1 0 {name=p338 sig_type=std_logic lab=H4}
C {devices/lab_pin.sym} 755 -870 2 1 {name=p344 sig_type=std_logic lab=H5}
C {devices/lab_pin.sym} 995 -910 1 0 {name=p350 sig_type=std_logic lab=H4}
C {devices/lab_pin.sym} 995 -870 2 1 {name=p356 sig_type=std_logic lab=H5}
C {devices/lab_pin.sym} 1235 -910 1 0 {name=p357 sig_type=std_logic lab=H4}
C {devices/lab_pin.sym} 1235 -870 2 1 {name=p358 sig_type=std_logic lab=H5}
C {devices/lab_pin.sym} 1475 -910 1 0 {name=p365 sig_type=std_logic lab=H4}
C {devices/lab_pin.sym} 1475 -870 2 1 {name=p371 sig_type=std_logic lab=H5}
C {devices/lab_pin.sym} 1715 -910 1 0 {name=p374 sig_type=std_logic lab=H4}
C {devices/lab_pin.sym} 1715 -870 2 1 {name=p380 sig_type=std_logic lab=H5}
C {devices/lab_pin.sym} 275 -685 1 0 {name=p389 sig_type=std_logic lab=H5}
C {devices/lab_pin.sym} 275 -645 2 1 {name=p395 sig_type=std_logic lab=H6}
C {devices/lab_pin.sym} 515 -685 1 0 {name=p402 sig_type=std_logic lab=H5}
C {devices/lab_pin.sym} 515 -645 2 1 {name=p403 sig_type=std_logic lab=H6}
C {devices/lab_pin.sym} 755 -685 1 0 {name=p410 sig_type=std_logic lab=H5}
C {devices/lab_pin.sym} 755 -645 2 1 {name=p416 sig_type=std_logic lab=H6}
C {devices/lab_pin.sym} 995 -685 1 0 {name=p422 sig_type=std_logic lab=H5}
C {devices/lab_pin.sym} 995 -645 2 1 {name=p428 sig_type=std_logic lab=H6}
C {devices/lab_pin.sym} 1235 -685 1 0 {name=p429 sig_type=std_logic lab=H5}
C {devices/lab_pin.sym} 1235 -645 2 1 {name=p430 sig_type=std_logic lab=H6}
C {devices/lab_pin.sym} 1475 -685 1 0 {name=p437 sig_type=std_logic lab=H5}
C {devices/lab_pin.sym} 1475 -645 2 1 {name=p443 sig_type=std_logic lab=H6}
C {devices/lab_pin.sym} 1715 -685 1 0 {name=p446 sig_type=std_logic lab=H5}
C {devices/lab_pin.sym} 1715 -645 2 1 {name=p452 sig_type=std_logic lab=H6}
C {devices/lab_pin.sym} 35 -460 1 0 {name=p455 sig_type=std_logic lab=H6}
C {devices/lab_pin.sym} 35 -420 2 1 {name=p471 sig_type=std_logic lab=H7}
C {devices/lab_pin.sym} 275 -450 1 0 {name=p571 sig_type=std_logic lab=H6}
C {devices/lab_pin.sym} 275 -430 2 1 {name=p572 sig_type=std_logic lab=H7}
C {devices/lab_pin.sym} 515 -450 1 0 {name=p573 sig_type=std_logic lab=H6}
C {devices/lab_pin.sym} 515 -430 2 1 {name=p574 sig_type=std_logic lab=H7}
C {devices/lab_pin.sym} 755 -450 1 0 {name=p575 sig_type=std_logic lab=H6}
C {devices/lab_pin.sym} 755 -430 2 1 {name=p576 sig_type=std_logic lab=H7}
C {devices/lab_pin.sym} 995 -450 1 0 {name=p577 sig_type=std_logic lab=H6}
C {devices/lab_pin.sym} 995 -430 2 1 {name=p578 sig_type=std_logic lab=H7}
C {devices/lab_pin.sym} 1235 -450 1 0 {name=p579 sig_type=std_logic lab=H6}
C {devices/lab_pin.sym} 1235 -430 2 1 {name=p580 sig_type=std_logic lab=H7}
C {devices/lab_pin.sym} 1475 -450 1 0 {name=p581 sig_type=std_logic lab=H6}
C {devices/lab_pin.sym} 1475 -430 2 1 {name=p582 sig_type=std_logic lab=H7}
C {devices/lab_pin.sym} 1715 -460 1 0 {name=p583 sig_type=std_logic lab=H6}
C {devices/lab_pin.sym} 1715 -420 2 1 {name=p584 sig_type=std_logic lab=H7}
C {devices/lab_pin.sym} 275 -235 1 0 {name=p585 sig_type=std_logic lab=H7}
C {devices/lab_pin.sym} 275 -195 2 1 {name=p586 sig_type=std_logic lab=0}
C {devices/lab_pin.sym} 515 -235 1 0 {name=p587 sig_type=std_logic lab=H7}
C {devices/lab_pin.sym} 515 -195 2 1 {name=p588 sig_type=std_logic lab=0}
C {devices/lab_pin.sym} 755 -235 1 0 {name=p589 sig_type=std_logic lab=H7}
C {devices/lab_pin.sym} 755 -195 2 1 {name=p590 sig_type=std_logic lab=0}
C {devices/lab_pin.sym} 995 -235 1 0 {name=p591 sig_type=std_logic lab=H7}
C {devices/lab_pin.sym} 995 -195 2 1 {name=p592 sig_type=std_logic lab=0}
C {devices/lab_pin.sym} 1235 -235 1 0 {name=p593 sig_type=std_logic lab=H7}
C {devices/lab_pin.sym} 1235 -195 2 1 {name=p594 sig_type=std_logic lab=0}
C {devices/lab_pin.sym} 1475 -235 1 0 {name=p595 sig_type=std_logic lab=H7}
C {devices/lab_pin.sym} 1475 -195 2 1 {name=p596 sig_type=std_logic lab=0}
C {devices/lab_pin.sym} 1715 -235 1 0 {name=p597 sig_type=std_logic lab=H7}
C {devices/lab_pin.sym} 1715 -195 2 1 {name=p598 sig_type=std_logic lab=0}
C {devices/title.sym} 165 -40 0 0 {name=l1 author="Junbeom Park"}
C {devices/vsource.sym} -1085 -400 0 0 {name=VDD1 
value="pulse 0 3.3 150n 0.1n 0.1n 159.8n 320n"
*value=0}
C {devices/vsource.sym} -1085 -495 0 0 {name=VDD2 
value="pulse 0 3.3 310n 0.1n 0.1n 319.8n 640n"
*value=0}
C {devices/vsource.sym} -1085 -590 0 0 {name=VDD3
value="pulse 0 3.3 630n 0.1n 0.1n 639.8n 1280n"
*value=0}
C {devices/lab_pin.sym} -1085 -560 2 1 {name=p601 sig_type=std_logic lab=0}
C {devices/lab_pin.sym} -1085 -465 2 1 {name=p602 sig_type=std_logic lab=0}
C {devices/lab_pin.sym} -1085 -370 2 1 {name=p603 sig_type=std_logic lab=0}
C {devices/lab_pin.sym} -1085 -430 0 1 {name=p604 sig_type=std_logic lab=Q4}
C {devices/lab_pin.sym} -1085 -525 0 1 {name=p605 sig_type=std_logic lab=Q5}
C {devices/lab_pin.sym} -1085 -620 0 1 {name=p606 sig_type=std_logic lab=Q6}
C {devices/lab_pin.sym} -355 -60 0 1 {name=p607 sig_type=std_logic lab=CLK}
C {devices/lab_pin.sym} -355 0 0 1 {name=p608 sig_type=std_logic lab=0}
C {devices/vsource.sym} -355 -30 0 0 {name=VDD5 value="pulse 0 3.3 0 0.1n 0.1n 4.8n 10n"
*value="pwl 0 0 9.9n 0 10n 3.3"}
C {devices/vsource.sym} -1085 -690 0 0 {name=VDD4 
value="pulse 0 3.3 1270n 0.1n 0.1n 1279.8n 2560n"
*value=0}
C {devices/vsource.sym} -1085 -785 0 0 {name=VDD6 
value="pulse 0 3.3 2550n 0.1n 0.1n 2559.8n 5120n"
*value=0}
C {devices/vsource.sym} -1085 -880 0 0 {name=VDD7 
value="pulse 0 3.3 5110n 0.1n 0.1n 5119.8n 10240n"
*value=0}
C {devices/lab_pin.sym} -1085 -850 2 1 {name=p609 sig_type=std_logic lab=0}
C {devices/lab_pin.sym} -1085 -755 2 1 {name=p610 sig_type=std_logic lab=0}
C {devices/lab_pin.sym} -1085 -660 2 1 {name=p611 sig_type=std_logic lab=0}
C {devices/lab_pin.sym} -1085 -720 0 1 {name=p612 sig_type=std_logic lab=Q7}
C {devices/lab_pin.sym} -1085 -815 0 1 {name=p613 sig_type=std_logic lab=Q8}
C {devices/lab_pin.sym} -1085 -910 0 1 {name=p614 sig_type=std_logic lab=Q9}
C {devices/vsource.sym} -570 -30 0 0 {name=VDD8 value=3.3}
C {devices/lab_pin.sym} -570 0 0 1 {name=p615 sig_type=std_logic lab=0}
C {devices/lab_pin.sym} -570 -60 0 1 {name=p616 sig_type=std_logic lab=vb1}
C {devices/vsource.sym} -500 -30 0 0 {name=VDD9 value=3.3}
C {devices/lab_pin.sym} -500 0 0 1 {name=p617 sig_type=std_logic lab=0}
C {devices/lab_pin.sym} -500 -60 0 1 {name=p618 sig_type=std_logic lab=vb2}
C {devices/lab_pin.sym} -125 -785 0 1 {name=p619 sig_type=std_logic lab=OUT+}
C {devices/vsource.sym} -140 -30 0 0 {name=VDD10 value=3.3}
C {devices/lab_pin.sym} -140 0 0 1 {name=p621 sig_type=std_logic lab=0}
C {devices/lab_pin.sym} -140 -60 0 1 {name=p622 sig_type=std_logic lab=AVDD}
C {devices/lab_pin.sym} -125 -960 2 0 {name=p623 sig_type=std_logic lab=AVDD}
C {devices/lab_pin.sym} -205 -960 2 1 {name=p624 sig_type=std_logic lab=AVDD}
C {devices/res.sym} -205 -905 0 0 {name=R-
value=50
footprint=1206
device=resistor
m=1}
C {devices/res.sym} -125 -905 0 0 {name=R+
value=50
footprint=1206
device=resistor
m=1}
C {devices/vsource.sym} -140 80 0 0 {name=VDD15 value=3.3}
C {devices/lab_pin.sym} -140 110 0 1 {name=p661 sig_type=std_logic lab=0}
C {devices/lab_pin.sym} -140 50 0 1 {name=p662 sig_type=std_logic lab=vdd}
C {devices/simulator_commands.sym} -595 -250 0 0 {name=COMMANDS1
only_toplevel=false
value="

.include /foss/pdks/gf180mcuC/libs.tech/ngspice/design.ngspice
.lib /foss/pdks/gf180mcuC/libs.tech/ngspice/sm141064.ngspice typical


.control
	tran 1n 1u
	plot v(Q0)
	plot v(Q1)
	plot v(Q2)
	plot v(Q3)
	plot v(Q4)
	plot v(Q5)
	plot v(Q6)
	plot v(Q7)
	plot v(Q8)
	plot v(Q9)
	plot i(Vmeas+)
	write topview.raw
.endc
.save all

"}
C {devices/lab_pin.sym} -205 -785 2 1 {name=p620 sig_type=std_logic lab=OUT-}
C {devices/vsource.sym} -1085 -295 0 0 {name=VDD11 
value="pulse 0 3.3 70n 0.1n 0.1n 79.8n 160n"
*value=0}
C {devices/lab_pin.sym} -1085 -325 0 1 {name=p625 sig_type=std_logic lab=Q3}
C {devices/lab_pin.sym} -1085 -265 2 1 {name=p626 sig_type=std_logic lab=0}
C {devices/vsource.sym} -1085 -205 0 0 {name=VDD12 
value="pulse 0 3.3 30n 0.1n 0.1n 39.8n 80n"
*value=0}
C {devices/lab_pin.sym} -1085 -235 0 1 {name=p627 sig_type=std_logic lab=Q2}
C {devices/lab_pin.sym} -1085 -175 2 1 {name=p628 sig_type=std_logic lab=0}
C {devices/vsource.sym} -1085 -115 0 0 {name=VDD13 
value="pulse 0 3.3 10n 0.1n 0.1n 19.8n 40n"
*value=0}
C {devices/lab_pin.sym} -1085 -145 0 1 {name=p629 sig_type=std_logic lab=Q1}
C {devices/lab_pin.sym} -1085 -85 2 1 {name=p630 sig_type=std_logic lab=0}
C {devices/vsource.sym} -1085 -25 0 0 {name=VDD14 
value="pulse 0 3.3 0 0.1n 0.1n 9.8n 20n"
*value=0}
C {devices/lab_pin.sym} -1085 -55 0 1 {name=p631 sig_type=std_logic lab=Q0}
C {devices/lab_pin.sym} -1085 5 2 1 {name=p632 sig_type=std_logic lab=0}
C {digtal/DLatch.sym} 2150 -1080 0 0 {name=x74}
C {devices/lab_pin.sym} 2130 -1130 1 0 {name=p633 sig_type=std_logic lab=Q3}
C {analog/current_unitx8.sym} 2290 -1100 0 0 {name=x3}
C {devices/lab_pin.sym} 2200 -1180 0 1 {name=p634 sig_type=std_logic lab=vdd}
C {devices/lab_pin.sym} 2200 -1080 1 1 {name=p635 sig_type=std_logic lab=CLK}
C {devices/lab_pin.sym} 2320 -1080 1 1 {name=p636 sig_type=std_logic lab=vb2}
C {devices/lab_pin.sym} 2340 -1080 1 1 {name=p637 sig_type=std_logic lab=vb1}
C {devices/lab_pin.sym} 2390 -1160 3 1 {name=p638 sig_type=std_logic lab=OUT+}
C {devices/lab_pin.sym} 2390 -1120 1 1 {name=p639 sig_type=std_logic lab=OUT-}
C {digtal/DLatch.sym} 2455 -1080 0 0 {name=x75}
C {devices/lab_pin.sym} 2435 -1130 1 0 {name=p640 sig_type=std_logic lab=Q2}
C {devices/lab_pin.sym} 2505 -1180 0 1 {name=p641 sig_type=std_logic lab=vdd}
C {devices/lab_pin.sym} 2505 -1080 1 1 {name=p642 sig_type=std_logic lab=CLK}
C {devices/lab_pin.sym} 2625 -1080 1 1 {name=p643 sig_type=std_logic lab=vb2}
C {devices/lab_pin.sym} 2645 -1080 1 1 {name=p644 sig_type=std_logic lab=vb1}
C {devices/lab_pin.sym} 2695 -1160 3 1 {name=p645 sig_type=std_logic lab=OUT+}
C {devices/lab_pin.sym} 2695 -1120 1 1 {name=p646 sig_type=std_logic lab=OUT-}
C {analog/current_unitx4.sym} 2595 -1100 0 0 {name=x68}
C {digtal/DLatch.sym} 2150 -785 0 0 {name=x73}
C {devices/lab_pin.sym} 2130 -835 1 0 {name=p647 sig_type=std_logic lab=Q1}
C {devices/lab_pin.sym} 2200 -885 0 1 {name=p648 sig_type=std_logic lab=vdd}
C {devices/lab_pin.sym} 2200 -785 1 1 {name=p649 sig_type=std_logic lab=CLK}
C {devices/lab_pin.sym} 2320 -785 1 1 {name=p650 sig_type=std_logic lab=vb2}
C {devices/lab_pin.sym} 2340 -785 1 1 {name=p651 sig_type=std_logic lab=vb1}
C {devices/lab_pin.sym} 2390 -865 3 1 {name=p652 sig_type=std_logic lab=OUT+}
C {devices/lab_pin.sym} 2390 -825 1 1 {name=p653 sig_type=std_logic lab=OUT-}
C {digtal/DLatch.sym} 2455 -785 0 0 {name=x77}
C {devices/lab_pin.sym} 2435 -835 1 0 {name=p654 sig_type=std_logic lab=Q0}
C {devices/lab_pin.sym} 2505 -885 0 1 {name=p655 sig_type=std_logic lab=vdd}
C {devices/lab_pin.sym} 2505 -785 1 1 {name=p656 sig_type=std_logic lab=CLK}
C {devices/lab_pin.sym} 2625 -785 1 1 {name=p657 sig_type=std_logic lab=vb2}
C {devices/lab_pin.sym} 2645 -785 1 1 {name=p658 sig_type=std_logic lab=vb1}
C {devices/lab_pin.sym} 2695 -865 3 1 {name=p659 sig_type=std_logic lab=OUT+}
C {devices/lab_pin.sym} 2695 -825 1 1 {name=p660 sig_type=std_logic lab=OUT-}
C {analog/array_cell.sym} 65 -1745 0 0 {name=x4}
C {analog/array_cell.sym} 295 -1750 0 0 {name=x5}
C {analog/array_cell.sym} 535 -1750 0 0 {name=x6}
C {analog/array_cell.sym} 775 -1750 0 0 {name=x7}
C {analog/array_cell.sym} 1015 -1750 0 0 {name=x8}
C {analog/array_cell.sym} 1255 -1750 0 0 {name=x9}
C {analog/array_cell.sym} 1495 -1750 0 0 {name=x10}
C {analog/array_cell.sym} 1735 -1750 0 0 {name=x67}
C {analog/current_unitx2.sym} 2270 -805 0 0 {name=x69}
C {analog/current_unitx1.sym} 2575 -785 0 0 {name=x70}
C {digtal/Dec3_7.sym} -245 -1870 2 1 {name=x1}
C {digtal/Dec3_7.sym} 35 -2110 1 0 {name=x2}
C {devices/ammeter.sym} -125 -845 0 0 {name=Vmeas+}
C {devices/ammeter.sym} -205 -845 0 0 {name=Vmeas-}
